VERSION 5.8 ;
BUSBITCHARS "[]" ;
DIVIDERCHAR "/" ;
UNITS
    DATABASE MICRONS 1000 ;
END UNITS

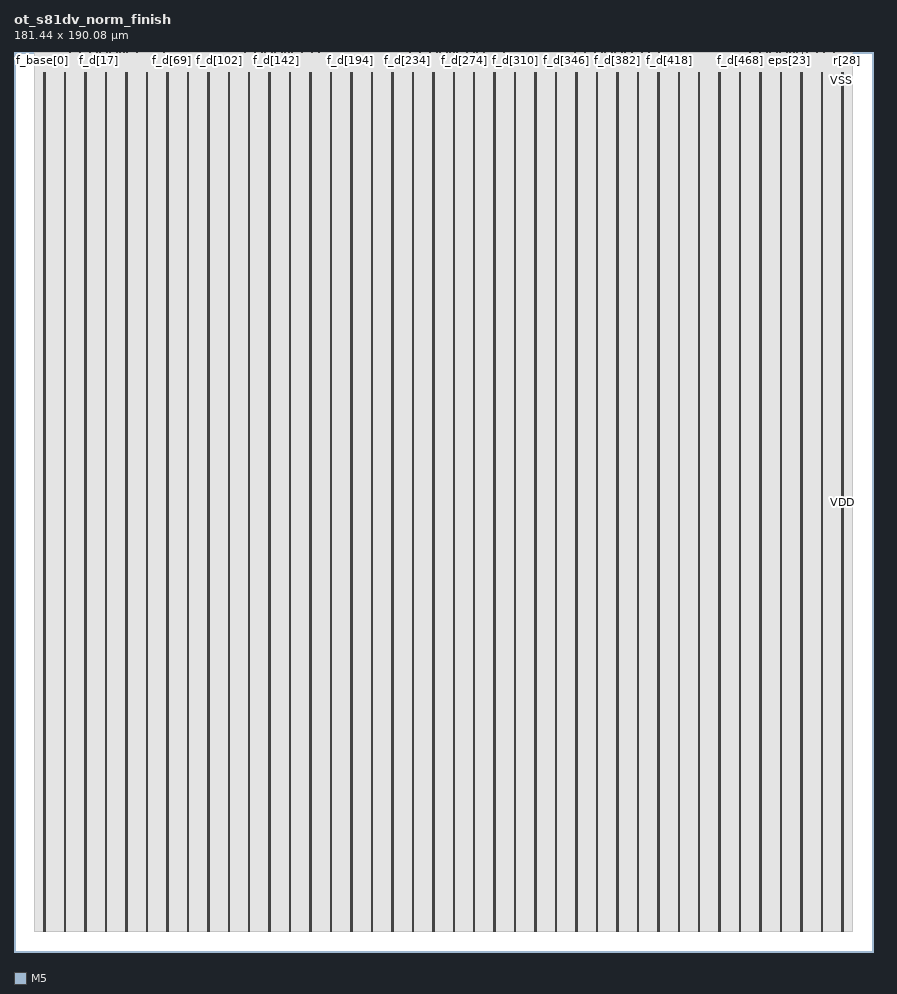
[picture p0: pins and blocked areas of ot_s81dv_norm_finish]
MACRO ot_s81dv_norm_finish
  FOREIGN ot_s81dv_norm_finish 0 0 ;
  CLASS BLOCK ;
  SIZE 181.44 BY 190.08 ;
  PIN clk
    DIRECTION INPUT ;
    USE SIGNAL ;
    PORT
      LAYER M5 ;
        RECT  166.548 189.6 166.596 190.08 ;
    END
  END clk
  PIN eps[0]
    DIRECTION INPUT ;
    USE SIGNAL ;
    PORT
      LAYER M5 ;
        RECT  156.96 189.996 156.984 190.08 ;
    END
  END eps[0]
  PIN eps[10]
    DIRECTION INPUT ;
    USE SIGNAL ;
    PORT
      LAYER M5 ;
        RECT  159.936 189.996 159.96 190.08 ;
    END
  END eps[10]
  PIN eps[11]
    DIRECTION INPUT ;
    USE SIGNAL ;
    PORT
      LAYER M5 ;
        RECT  160.224 189.996 160.248 190.08 ;
    END
  END eps[11]
  PIN eps[12]
    DIRECTION INPUT ;
    USE SIGNAL ;
    PORT
      LAYER M5 ;
        RECT  160.56 189.996 160.584 190.08 ;
    END
  END eps[12]
  PIN eps[13]
    DIRECTION INPUT ;
    USE SIGNAL ;
    PORT
      LAYER M5 ;
        RECT  160.848 189.996 160.872 190.08 ;
    END
  END eps[13]
  PIN eps[14]
    DIRECTION INPUT ;
    USE SIGNAL ;
    PORT
      LAYER M5 ;
        RECT  161.136 189.996 161.16 190.08 ;
    END
  END eps[14]
  PIN eps[15]
    DIRECTION INPUT ;
    USE SIGNAL ;
    PORT
      LAYER M5 ;
        RECT  161.472 189.996 161.496 190.08 ;
    END
  END eps[15]
  PIN eps[16]
    DIRECTION INPUT ;
    USE SIGNAL ;
    PORT
      LAYER M5 ;
        RECT  161.76 189.996 161.784 190.08 ;
    END
  END eps[16]
  PIN eps[17]
    DIRECTION INPUT ;
    USE SIGNAL ;
    PORT
      LAYER M5 ;
        RECT  162.048 189.996 162.072 190.08 ;
    END
  END eps[17]
  PIN eps[18]
    DIRECTION INPUT ;
    USE SIGNAL ;
    PORT
      LAYER M5 ;
        RECT  162.336 189.996 162.36 190.08 ;
    END
  END eps[18]
  PIN eps[19]
    DIRECTION INPUT ;
    USE SIGNAL ;
    PORT
      LAYER M5 ;
        RECT  162.672 189.996 162.696 190.08 ;
    END
  END eps[19]
  PIN eps[1]
    DIRECTION INPUT ;
    USE SIGNAL ;
    PORT
      LAYER M5 ;
        RECT  157.248 189.996 157.272 190.08 ;
    END
  END eps[1]
  PIN eps[20]
    DIRECTION INPUT ;
    USE SIGNAL ;
    PORT
      LAYER M5 ;
        RECT  162.96 189.996 162.984 190.08 ;
    END
  END eps[20]
  PIN eps[21]
    DIRECTION INPUT ;
    USE SIGNAL ;
    PORT
      LAYER M5 ;
        RECT  163.248 189.996 163.272 190.08 ;
    END
  END eps[21]
  PIN eps[22]
    DIRECTION INPUT ;
    USE SIGNAL ;
    PORT
      LAYER M5 ;
        RECT  163.536 189.996 163.56 190.08 ;
    END
  END eps[22]
  PIN eps[23]
    DIRECTION INPUT ;
    USE SIGNAL ;
    PORT
      LAYER M5 ;
        RECT  163.872 189.996 163.896 190.08 ;
    END
  END eps[23]
  PIN eps[24]
    DIRECTION INPUT ;
    USE SIGNAL ;
    PORT
      LAYER M5 ;
        RECT  164.16 189.996 164.184 190.08 ;
    END
  END eps[24]
  PIN eps[25]
    DIRECTION INPUT ;
    USE SIGNAL ;
    PORT
      LAYER M5 ;
        RECT  164.448 189.996 164.472 190.08 ;
    END
  END eps[25]
  PIN eps[26]
    DIRECTION INPUT ;
    USE SIGNAL ;
    PORT
      LAYER M5 ;
        RECT  164.736 189.996 164.76 190.08 ;
    END
  END eps[26]
  PIN eps[27]
    DIRECTION INPUT ;
    USE SIGNAL ;
    PORT
      LAYER M5 ;
        RECT  165.072 189.996 165.096 190.08 ;
    END
  END eps[27]
  PIN eps[28]
    DIRECTION INPUT ;
    USE SIGNAL ;
    PORT
      LAYER M5 ;
        RECT  165.36 189.996 165.384 190.08 ;
    END
  END eps[28]
  PIN eps[29]
    DIRECTION INPUT ;
    USE SIGNAL ;
    PORT
      LAYER M5 ;
        RECT  165.648 189.996 165.672 190.08 ;
    END
  END eps[29]
  PIN eps[2]
    DIRECTION INPUT ;
    USE SIGNAL ;
    PORT
      LAYER M5 ;
        RECT  157.536 189.996 157.56 190.08 ;
    END
  END eps[2]
  PIN eps[30]
    DIRECTION INPUT ;
    USE SIGNAL ;
    PORT
      LAYER M5 ;
        RECT  165.936 189.996 165.96 190.08 ;
    END
  END eps[30]
  PIN eps[31]
    DIRECTION INPUT ;
    USE SIGNAL ;
    PORT
      LAYER M5 ;
        RECT  166.272 189.996 166.296 190.08 ;
    END
  END eps[31]
  PIN eps[3]
    DIRECTION INPUT ;
    USE SIGNAL ;
    PORT
      LAYER M5 ;
        RECT  157.824 189.996 157.848 190.08 ;
    END
  END eps[3]
  PIN eps[4]
    DIRECTION INPUT ;
    USE SIGNAL ;
    PORT
      LAYER M5 ;
        RECT  158.16 189.996 158.184 190.08 ;
    END
  END eps[4]
  PIN eps[5]
    DIRECTION INPUT ;
    USE SIGNAL ;
    PORT
      LAYER M5 ;
        RECT  158.448 189.996 158.472 190.08 ;
    END
  END eps[5]
  PIN eps[6]
    DIRECTION INPUT ;
    USE SIGNAL ;
    PORT
      LAYER M5 ;
        RECT  158.736 189.996 158.76 190.08 ;
    END
  END eps[6]
  PIN eps[7]
    DIRECTION INPUT ;
    USE SIGNAL ;
    PORT
      LAYER M5 ;
        RECT  159.024 189.996 159.048 190.08 ;
    END
  END eps[7]
  PIN eps[8]
    DIRECTION INPUT ;
    USE SIGNAL ;
    PORT
      LAYER M5 ;
        RECT  159.36 189.996 159.384 190.08 ;
    END
  END eps[8]
  PIN eps[9]
    DIRECTION INPUT ;
    USE SIGNAL ;
    PORT
      LAYER M5 ;
        RECT  159.648 189.996 159.672 190.08 ;
    END
  END eps[9]
  PIN f_base[0]
    DIRECTION INPUT ;
    USE SIGNAL ;
    PORT
      LAYER M5 ;
        RECT  5.52 189.996 5.544 190.08 ;
    END
  END f_base[0]
  PIN f_base[10]
    DIRECTION INPUT ;
    USE SIGNAL ;
    PORT
      LAYER M5 ;
        RECT  8.544 189.996 8.568 190.08 ;
    END
  END f_base[10]
  PIN f_base[11]
    DIRECTION INPUT ;
    USE SIGNAL ;
    PORT
      LAYER M5 ;
        RECT  8.832 189.996 8.856 190.08 ;
    END
  END f_base[11]
  PIN f_base[12]
    DIRECTION INPUT ;
    USE SIGNAL ;
    PORT
      LAYER M5 ;
        RECT  9.12 189.996 9.144 190.08 ;
    END
  END f_base[12]
  PIN f_base[13]
    DIRECTION INPUT ;
    USE SIGNAL ;
    PORT
      LAYER M5 ;
        RECT  9.408 189.996 9.432 190.08 ;
    END
  END f_base[13]
  PIN f_base[14]
    DIRECTION INPUT ;
    USE SIGNAL ;
    PORT
      LAYER M5 ;
        RECT  9.744 189.996 9.768 190.08 ;
    END
  END f_base[14]
  PIN f_base[15]
    DIRECTION INPUT ;
    USE SIGNAL ;
    PORT
      LAYER M5 ;
        RECT  10.032 189.996 10.056 190.08 ;
    END
  END f_base[15]
  PIN f_base[16]
    DIRECTION INPUT ;
    USE SIGNAL ;
    PORT
      LAYER M5 ;
        RECT  10.32 189.996 10.344 190.08 ;
    END
  END f_base[16]
  PIN f_base[17]
    DIRECTION INPUT ;
    USE SIGNAL ;
    PORT
      LAYER M5 ;
        RECT  10.608 189.996 10.632 190.08 ;
    END
  END f_base[17]
  PIN f_base[18]
    DIRECTION INPUT ;
    USE SIGNAL ;
    PORT
      LAYER M5 ;
        RECT  10.944 189.996 10.968 190.08 ;
    END
  END f_base[18]
  PIN f_base[19]
    DIRECTION INPUT ;
    USE SIGNAL ;
    PORT
      LAYER M5 ;
        RECT  11.232 189.996 11.256 190.08 ;
    END
  END f_base[19]
  PIN f_base[1]
    DIRECTION INPUT ;
    USE SIGNAL ;
    PORT
      LAYER M5 ;
        RECT  5.808 189.996 5.832 190.08 ;
    END
  END f_base[1]
  PIN f_base[20]
    DIRECTION INPUT ;
    USE SIGNAL ;
    PORT
      LAYER M5 ;
        RECT  11.52 189.996 11.544 190.08 ;
    END
  END f_base[20]
  PIN f_base[21]
    DIRECTION INPUT ;
    USE SIGNAL ;
    PORT
      LAYER M5 ;
        RECT  11.808 189.996 11.832 190.08 ;
    END
  END f_base[21]
  PIN f_base[22]
    DIRECTION INPUT ;
    USE SIGNAL ;
    PORT
      LAYER M5 ;
        RECT  12.144 189.996 12.168 190.08 ;
    END
  END f_base[22]
  PIN f_base[23]
    DIRECTION INPUT ;
    USE SIGNAL ;
    PORT
      LAYER M5 ;
        RECT  12.432 189.996 12.456 190.08 ;
    END
  END f_base[23]
  PIN f_base[2]
    DIRECTION INPUT ;
    USE SIGNAL ;
    PORT
      LAYER M5 ;
        RECT  6.144 189.996 6.168 190.08 ;
    END
  END f_base[2]
  PIN f_base[3]
    DIRECTION INPUT ;
    USE SIGNAL ;
    PORT
      LAYER M5 ;
        RECT  6.432 189.996 6.456 190.08 ;
    END
  END f_base[3]
  PIN f_base[4]
    DIRECTION INPUT ;
    USE SIGNAL ;
    PORT
      LAYER M5 ;
        RECT  6.72 189.996 6.744 190.08 ;
    END
  END f_base[4]
  PIN f_base[5]
    DIRECTION INPUT ;
    USE SIGNAL ;
    PORT
      LAYER M5 ;
        RECT  7.008 189.996 7.032 190.08 ;
    END
  END f_base[5]
  PIN f_base[6]
    DIRECTION INPUT ;
    USE SIGNAL ;
    PORT
      LAYER M5 ;
        RECT  7.344 189.996 7.368 190.08 ;
    END
  END f_base[6]
  PIN f_base[7]
    DIRECTION INPUT ;
    USE SIGNAL ;
    PORT
      LAYER M5 ;
        RECT  7.632 189.996 7.656 190.08 ;
    END
  END f_base[7]
  PIN f_base[8]
    DIRECTION INPUT ;
    USE SIGNAL ;
    PORT
      LAYER M5 ;
        RECT  7.92 189.996 7.944 190.08 ;
    END
  END f_base[8]
  PIN f_base[9]
    DIRECTION INPUT ;
    USE SIGNAL ;
    PORT
      LAYER M5 ;
        RECT  8.208 189.996 8.232 190.08 ;
    END
  END f_base[9]
  PIN f_d[0]
    DIRECTION INPUT ;
    USE SIGNAL ;
    PORT
      LAYER M5 ;
        RECT  12.72 189.996 12.744 190.08 ;
    END
  END f_d[0]
  PIN f_d[100]
    DIRECTION INPUT ;
    USE SIGNAL ;
    PORT
      LAYER M5 ;
        RECT  42.768 189.996 42.792 190.08 ;
    END
  END f_d[100]
  PIN f_d[101]
    DIRECTION INPUT ;
    USE SIGNAL ;
    PORT
      LAYER M5 ;
        RECT  43.056 189.996 43.08 190.08 ;
    END
  END f_d[101]
  PIN f_d[102]
    DIRECTION INPUT ;
    USE SIGNAL ;
    PORT
      LAYER M5 ;
        RECT  43.392 189.996 43.416 190.08 ;
    END
  END f_d[102]
  PIN f_d[103]
    DIRECTION INPUT ;
    USE SIGNAL ;
    PORT
      LAYER M5 ;
        RECT  43.68 189.996 43.704 190.08 ;
    END
  END f_d[103]
  PIN f_d[104]
    DIRECTION INPUT ;
    USE SIGNAL ;
    PORT
      LAYER M5 ;
        RECT  43.968 189.996 43.992 190.08 ;
    END
  END f_d[104]
  PIN f_d[105]
    DIRECTION INPUT ;
    USE SIGNAL ;
    PORT
      LAYER M5 ;
        RECT  44.256 189.996 44.28 190.08 ;
    END
  END f_d[105]
  PIN f_d[106]
    DIRECTION INPUT ;
    USE SIGNAL ;
    PORT
      LAYER M5 ;
        RECT  44.592 189.996 44.616 190.08 ;
    END
  END f_d[106]
  PIN f_d[107]
    DIRECTION INPUT ;
    USE SIGNAL ;
    PORT
      LAYER M5 ;
        RECT  44.88 189.996 44.904 190.08 ;
    END
  END f_d[107]
  PIN f_d[108]
    DIRECTION INPUT ;
    USE SIGNAL ;
    PORT
      LAYER M5 ;
        RECT  45.168 189.996 45.192 190.08 ;
    END
  END f_d[108]
  PIN f_d[109]
    DIRECTION INPUT ;
    USE SIGNAL ;
    PORT
      LAYER M5 ;
        RECT  45.504 189.996 45.528 190.08 ;
    END
  END f_d[109]
  PIN f_d[10]
    DIRECTION INPUT ;
    USE SIGNAL ;
    PORT
      LAYER M5 ;
        RECT  15.744 189.996 15.768 190.08 ;
    END
  END f_d[10]
  PIN f_d[110]
    DIRECTION INPUT ;
    USE SIGNAL ;
    PORT
      LAYER M5 ;
        RECT  45.792 189.996 45.816 190.08 ;
    END
  END f_d[110]
  PIN f_d[111]
    DIRECTION INPUT ;
    USE SIGNAL ;
    PORT
      LAYER M5 ;
        RECT  46.08 189.996 46.104 190.08 ;
    END
  END f_d[111]
  PIN f_d[112]
    DIRECTION INPUT ;
    USE SIGNAL ;
    PORT
      LAYER M5 ;
        RECT  46.368 189.996 46.392 190.08 ;
    END
  END f_d[112]
  PIN f_d[113]
    DIRECTION INPUT ;
    USE SIGNAL ;
    PORT
      LAYER M5 ;
        RECT  46.704 189.996 46.728 190.08 ;
    END
  END f_d[113]
  PIN f_d[114]
    DIRECTION INPUT ;
    USE SIGNAL ;
    PORT
      LAYER M5 ;
        RECT  46.992 189.996 47.016 190.08 ;
    END
  END f_d[114]
  PIN f_d[115]
    DIRECTION INPUT ;
    USE SIGNAL ;
    PORT
      LAYER M5 ;
        RECT  47.28 189.996 47.304 190.08 ;
    END
  END f_d[115]
  PIN f_d[116]
    DIRECTION INPUT ;
    USE SIGNAL ;
    PORT
      LAYER M5 ;
        RECT  47.568 189.996 47.592 190.08 ;
    END
  END f_d[116]
  PIN f_d[117]
    DIRECTION INPUT ;
    USE SIGNAL ;
    PORT
      LAYER M5 ;
        RECT  47.904 189.996 47.928 190.08 ;
    END
  END f_d[117]
  PIN f_d[118]
    DIRECTION INPUT ;
    USE SIGNAL ;
    PORT
      LAYER M5 ;
        RECT  48.192 189.996 48.216 190.08 ;
    END
  END f_d[118]
  PIN f_d[119]
    DIRECTION INPUT ;
    USE SIGNAL ;
    PORT
      LAYER M5 ;
        RECT  48.48 189.996 48.504 190.08 ;
    END
  END f_d[119]
  PIN f_d[11]
    DIRECTION INPUT ;
    USE SIGNAL ;
    PORT
      LAYER M5 ;
        RECT  16.032 189.996 16.056 190.08 ;
    END
  END f_d[11]
  PIN f_d[120]
    DIRECTION INPUT ;
    USE SIGNAL ;
    PORT
      LAYER M5 ;
        RECT  48.768 189.996 48.792 190.08 ;
    END
  END f_d[120]
  PIN f_d[121]
    DIRECTION INPUT ;
    USE SIGNAL ;
    PORT
      LAYER M5 ;
        RECT  49.104 189.996 49.128 190.08 ;
    END
  END f_d[121]
  PIN f_d[122]
    DIRECTION INPUT ;
    USE SIGNAL ;
    PORT
      LAYER M5 ;
        RECT  49.392 189.996 49.416 190.08 ;
    END
  END f_d[122]
  PIN f_d[123]
    DIRECTION INPUT ;
    USE SIGNAL ;
    PORT
      LAYER M5 ;
        RECT  49.68 189.996 49.704 190.08 ;
    END
  END f_d[123]
  PIN f_d[124]
    DIRECTION INPUT ;
    USE SIGNAL ;
    PORT
      LAYER M5 ;
        RECT  49.968 189.996 49.992 190.08 ;
    END
  END f_d[124]
  PIN f_d[125]
    DIRECTION INPUT ;
    USE SIGNAL ;
    PORT
      LAYER M5 ;
        RECT  50.304 189.996 50.328 190.08 ;
    END
  END f_d[125]
  PIN f_d[126]
    DIRECTION INPUT ;
    USE SIGNAL ;
    PORT
      LAYER M5 ;
        RECT  50.592 189.996 50.616 190.08 ;
    END
  END f_d[126]
  PIN f_d[127]
    DIRECTION INPUT ;
    USE SIGNAL ;
    PORT
      LAYER M5 ;
        RECT  50.88 189.996 50.904 190.08 ;
    END
  END f_d[127]
  PIN f_d[128]
    DIRECTION INPUT ;
    USE SIGNAL ;
    PORT
      LAYER M5 ;
        RECT  51.168 189.996 51.192 190.08 ;
    END
  END f_d[128]
  PIN f_d[129]
    DIRECTION INPUT ;
    USE SIGNAL ;
    PORT
      LAYER M5 ;
        RECT  51.504 189.996 51.528 190.08 ;
    END
  END f_d[129]
  PIN f_d[12]
    DIRECTION INPUT ;
    USE SIGNAL ;
    PORT
      LAYER M5 ;
        RECT  16.32 189.996 16.344 190.08 ;
    END
  END f_d[12]
  PIN f_d[130]
    DIRECTION INPUT ;
    USE SIGNAL ;
    PORT
      LAYER M5 ;
        RECT  51.792 189.996 51.816 190.08 ;
    END
  END f_d[130]
  PIN f_d[131]
    DIRECTION INPUT ;
    USE SIGNAL ;
    PORT
      LAYER M5 ;
        RECT  52.08 189.996 52.104 190.08 ;
    END
  END f_d[131]
  PIN f_d[132]
    DIRECTION INPUT ;
    USE SIGNAL ;
    PORT
      LAYER M5 ;
        RECT  52.368 189.996 52.392 190.08 ;
    END
  END f_d[132]
  PIN f_d[133]
    DIRECTION INPUT ;
    USE SIGNAL ;
    PORT
      LAYER M5 ;
        RECT  52.704 189.996 52.728 190.08 ;
    END
  END f_d[133]
  PIN f_d[134]
    DIRECTION INPUT ;
    USE SIGNAL ;
    PORT
      LAYER M5 ;
        RECT  52.992 189.996 53.016 190.08 ;
    END
  END f_d[134]
  PIN f_d[135]
    DIRECTION INPUT ;
    USE SIGNAL ;
    PORT
      LAYER M5 ;
        RECT  53.28 189.996 53.304 190.08 ;
    END
  END f_d[135]
  PIN f_d[136]
    DIRECTION INPUT ;
    USE SIGNAL ;
    PORT
      LAYER M5 ;
        RECT  53.568 189.996 53.592 190.08 ;
    END
  END f_d[136]
  PIN f_d[137]
    DIRECTION INPUT ;
    USE SIGNAL ;
    PORT
      LAYER M5 ;
        RECT  53.904 189.996 53.928 190.08 ;
    END
  END f_d[137]
  PIN f_d[138]
    DIRECTION INPUT ;
    USE SIGNAL ;
    PORT
      LAYER M5 ;
        RECT  54.192 189.996 54.216 190.08 ;
    END
  END f_d[138]
  PIN f_d[139]
    DIRECTION INPUT ;
    USE SIGNAL ;
    PORT
      LAYER M5 ;
        RECT  54.48 189.996 54.504 190.08 ;
    END
  END f_d[139]
  PIN f_d[13]
    DIRECTION INPUT ;
    USE SIGNAL ;
    PORT
      LAYER M5 ;
        RECT  16.656 189.996 16.68 190.08 ;
    END
  END f_d[13]
  PIN f_d[140]
    DIRECTION INPUT ;
    USE SIGNAL ;
    PORT
      LAYER M5 ;
        RECT  54.816 189.996 54.84 190.08 ;
    END
  END f_d[140]
  PIN f_d[141]
    DIRECTION INPUT ;
    USE SIGNAL ;
    PORT
      LAYER M5 ;
        RECT  55.104 189.996 55.128 190.08 ;
    END
  END f_d[141]
  PIN f_d[142]
    DIRECTION INPUT ;
    USE SIGNAL ;
    PORT
      LAYER M5 ;
        RECT  55.392 189.996 55.416 190.08 ;
    END
  END f_d[142]
  PIN f_d[143]
    DIRECTION INPUT ;
    USE SIGNAL ;
    PORT
      LAYER M5 ;
        RECT  55.68 189.996 55.704 190.08 ;
    END
  END f_d[143]
  PIN f_d[144]
    DIRECTION INPUT ;
    USE SIGNAL ;
    PORT
      LAYER M5 ;
        RECT  56.016 189.996 56.04 190.08 ;
    END
  END f_d[144]
  PIN f_d[145]
    DIRECTION INPUT ;
    USE SIGNAL ;
    PORT
      LAYER M5 ;
        RECT  56.304 189.996 56.328 190.08 ;
    END
  END f_d[145]
  PIN f_d[146]
    DIRECTION INPUT ;
    USE SIGNAL ;
    PORT
      LAYER M5 ;
        RECT  56.592 189.996 56.616 190.08 ;
    END
  END f_d[146]
  PIN f_d[147]
    DIRECTION INPUT ;
    USE SIGNAL ;
    PORT
      LAYER M5 ;
        RECT  56.88 189.996 56.904 190.08 ;
    END
  END f_d[147]
  PIN f_d[148]
    DIRECTION INPUT ;
    USE SIGNAL ;
    PORT
      LAYER M5 ;
        RECT  57.216 189.996 57.24 190.08 ;
    END
  END f_d[148]
  PIN f_d[149]
    DIRECTION INPUT ;
    USE SIGNAL ;
    PORT
      LAYER M5 ;
        RECT  57.504 189.996 57.528 190.08 ;
    END
  END f_d[149]
  PIN f_d[14]
    DIRECTION INPUT ;
    USE SIGNAL ;
    PORT
      LAYER M5 ;
        RECT  16.944 189.996 16.968 190.08 ;
    END
  END f_d[14]
  PIN f_d[150]
    DIRECTION INPUT ;
    USE SIGNAL ;
    PORT
      LAYER M5 ;
        RECT  57.792 189.996 57.816 190.08 ;
    END
  END f_d[150]
  PIN f_d[151]
    DIRECTION INPUT ;
    USE SIGNAL ;
    PORT
      LAYER M5 ;
        RECT  58.08 189.996 58.104 190.08 ;
    END
  END f_d[151]
  PIN f_d[152]
    DIRECTION INPUT ;
    USE SIGNAL ;
    PORT
      LAYER M5 ;
        RECT  58.416 189.996 58.44 190.08 ;
    END
  END f_d[152]
  PIN f_d[153]
    DIRECTION INPUT ;
    USE SIGNAL ;
    PORT
      LAYER M5 ;
        RECT  58.704 189.996 58.728 190.08 ;
    END
  END f_d[153]
  PIN f_d[154]
    DIRECTION INPUT ;
    USE SIGNAL ;
    PORT
      LAYER M5 ;
        RECT  58.992 189.996 59.016 190.08 ;
    END
  END f_d[154]
  PIN f_d[155]
    DIRECTION INPUT ;
    USE SIGNAL ;
    PORT
      LAYER M5 ;
        RECT  59.28 189.996 59.304 190.08 ;
    END
  END f_d[155]
  PIN f_d[156]
    DIRECTION INPUT ;
    USE SIGNAL ;
    PORT
      LAYER M5 ;
        RECT  59.616 189.996 59.64 190.08 ;
    END
  END f_d[156]
  PIN f_d[157]
    DIRECTION INPUT ;
    USE SIGNAL ;
    PORT
      LAYER M5 ;
        RECT  59.904 189.996 59.928 190.08 ;
    END
  END f_d[157]
  PIN f_d[158]
    DIRECTION INPUT ;
    USE SIGNAL ;
    PORT
      LAYER M5 ;
        RECT  60.192 189.996 60.216 190.08 ;
    END
  END f_d[158]
  PIN f_d[159]
    DIRECTION INPUT ;
    USE SIGNAL ;
    PORT
      LAYER M5 ;
        RECT  60.48 189.996 60.504 190.08 ;
    END
  END f_d[159]
  PIN f_d[15]
    DIRECTION INPUT ;
    USE SIGNAL ;
    PORT
      LAYER M5 ;
        RECT  17.232 189.996 17.256 190.08 ;
    END
  END f_d[15]
  PIN f_d[160]
    DIRECTION INPUT ;
    USE SIGNAL ;
    PORT
      LAYER M5 ;
        RECT  60.816 189.996 60.84 190.08 ;
    END
  END f_d[160]
  PIN f_d[161]
    DIRECTION INPUT ;
    USE SIGNAL ;
    PORT
      LAYER M5 ;
        RECT  61.104 189.996 61.128 190.08 ;
    END
  END f_d[161]
  PIN f_d[162]
    DIRECTION INPUT ;
    USE SIGNAL ;
    PORT
      LAYER M5 ;
        RECT  61.392 189.996 61.416 190.08 ;
    END
  END f_d[162]
  PIN f_d[163]
    DIRECTION INPUT ;
    USE SIGNAL ;
    PORT
      LAYER M5 ;
        RECT  61.68 189.996 61.704 190.08 ;
    END
  END f_d[163]
  PIN f_d[164]
    DIRECTION INPUT ;
    USE SIGNAL ;
    PORT
      LAYER M5 ;
        RECT  62.016 189.996 62.04 190.08 ;
    END
  END f_d[164]
  PIN f_d[165]
    DIRECTION INPUT ;
    USE SIGNAL ;
    PORT
      LAYER M5 ;
        RECT  62.304 189.996 62.328 190.08 ;
    END
  END f_d[165]
  PIN f_d[166]
    DIRECTION INPUT ;
    USE SIGNAL ;
    PORT
      LAYER M5 ;
        RECT  62.592 189.996 62.616 190.08 ;
    END
  END f_d[166]
  PIN f_d[167]
    DIRECTION INPUT ;
    USE SIGNAL ;
    PORT
      LAYER M5 ;
        RECT  62.928 189.996 62.952 190.08 ;
    END
  END f_d[167]
  PIN f_d[168]
    DIRECTION INPUT ;
    USE SIGNAL ;
    PORT
      LAYER M5 ;
        RECT  63.216 189.996 63.24 190.08 ;
    END
  END f_d[168]
  PIN f_d[169]
    DIRECTION INPUT ;
    USE SIGNAL ;
    PORT
      LAYER M5 ;
        RECT  63.504 189.996 63.528 190.08 ;
    END
  END f_d[169]
  PIN f_d[16]
    DIRECTION INPUT ;
    USE SIGNAL ;
    PORT
      LAYER M5 ;
        RECT  17.52 189.996 17.544 190.08 ;
    END
  END f_d[16]
  PIN f_d[170]
    DIRECTION INPUT ;
    USE SIGNAL ;
    PORT
      LAYER M5 ;
        RECT  63.792 189.996 63.816 190.08 ;
    END
  END f_d[170]
  PIN f_d[171]
    DIRECTION INPUT ;
    USE SIGNAL ;
    PORT
      LAYER M5 ;
        RECT  64.128 189.996 64.152 190.08 ;
    END
  END f_d[171]
  PIN f_d[172]
    DIRECTION INPUT ;
    USE SIGNAL ;
    PORT
      LAYER M5 ;
        RECT  64.416 189.996 64.44 190.08 ;
    END
  END f_d[172]
  PIN f_d[173]
    DIRECTION INPUT ;
    USE SIGNAL ;
    PORT
      LAYER M5 ;
        RECT  64.704 189.996 64.728 190.08 ;
    END
  END f_d[173]
  PIN f_d[174]
    DIRECTION INPUT ;
    USE SIGNAL ;
    PORT
      LAYER M5 ;
        RECT  64.992 189.996 65.016 190.08 ;
    END
  END f_d[174]
  PIN f_d[175]
    DIRECTION INPUT ;
    USE SIGNAL ;
    PORT
      LAYER M5 ;
        RECT  65.328 189.996 65.352 190.08 ;
    END
  END f_d[175]
  PIN f_d[176]
    DIRECTION INPUT ;
    USE SIGNAL ;
    PORT
      LAYER M5 ;
        RECT  65.616 189.996 65.64 190.08 ;
    END
  END f_d[176]
  PIN f_d[177]
    DIRECTION INPUT ;
    USE SIGNAL ;
    PORT
      LAYER M5 ;
        RECT  65.904 189.996 65.928 190.08 ;
    END
  END f_d[177]
  PIN f_d[178]
    DIRECTION INPUT ;
    USE SIGNAL ;
    PORT
      LAYER M5 ;
        RECT  66.192 189.996 66.216 190.08 ;
    END
  END f_d[178]
  PIN f_d[179]
    DIRECTION INPUT ;
    USE SIGNAL ;
    PORT
      LAYER M5 ;
        RECT  66.528 189.996 66.552 190.08 ;
    END
  END f_d[179]
  PIN f_d[17]
    DIRECTION INPUT ;
    USE SIGNAL ;
    PORT
      LAYER M5 ;
        RECT  17.856 189.996 17.88 190.08 ;
    END
  END f_d[17]
  PIN f_d[180]
    DIRECTION INPUT ;
    USE SIGNAL ;
    PORT
      LAYER M5 ;
        RECT  66.816 189.996 66.84 190.08 ;
    END
  END f_d[180]
  PIN f_d[181]
    DIRECTION INPUT ;
    USE SIGNAL ;
    PORT
      LAYER M5 ;
        RECT  67.104 189.996 67.128 190.08 ;
    END
  END f_d[181]
  PIN f_d[182]
    DIRECTION INPUT ;
    USE SIGNAL ;
    PORT
      LAYER M5 ;
        RECT  67.392 189.996 67.416 190.08 ;
    END
  END f_d[182]
  PIN f_d[183]
    DIRECTION INPUT ;
    USE SIGNAL ;
    PORT
      LAYER M5 ;
        RECT  67.728 189.996 67.752 190.08 ;
    END
  END f_d[183]
  PIN f_d[184]
    DIRECTION INPUT ;
    USE SIGNAL ;
    PORT
      LAYER M5 ;
        RECT  68.016 189.996 68.04 190.08 ;
    END
  END f_d[184]
  PIN f_d[185]
    DIRECTION INPUT ;
    USE SIGNAL ;
    PORT
      LAYER M5 ;
        RECT  68.304 189.996 68.328 190.08 ;
    END
  END f_d[185]
  PIN f_d[186]
    DIRECTION INPUT ;
    USE SIGNAL ;
    PORT
      LAYER M5 ;
        RECT  68.592 189.996 68.616 190.08 ;
    END
  END f_d[186]
  PIN f_d[187]
    DIRECTION INPUT ;
    USE SIGNAL ;
    PORT
      LAYER M5 ;
        RECT  68.928 189.996 68.952 190.08 ;
    END
  END f_d[187]
  PIN f_d[188]
    DIRECTION INPUT ;
    USE SIGNAL ;
    PORT
      LAYER M5 ;
        RECT  69.216 189.996 69.24 190.08 ;
    END
  END f_d[188]
  PIN f_d[189]
    DIRECTION INPUT ;
    USE SIGNAL ;
    PORT
      LAYER M5 ;
        RECT  69.504 189.996 69.528 190.08 ;
    END
  END f_d[189]
  PIN f_d[18]
    DIRECTION INPUT ;
    USE SIGNAL ;
    PORT
      LAYER M5 ;
        RECT  18.144 189.996 18.168 190.08 ;
    END
  END f_d[18]
  PIN f_d[190]
    DIRECTION INPUT ;
    USE SIGNAL ;
    PORT
      LAYER M5 ;
        RECT  69.792 189.996 69.816 190.08 ;
    END
  END f_d[190]
  PIN f_d[191]
    DIRECTION INPUT ;
    USE SIGNAL ;
    PORT
      LAYER M5 ;
        RECT  70.128 189.996 70.152 190.08 ;
    END
  END f_d[191]
  PIN f_d[192]
    DIRECTION INPUT ;
    USE SIGNAL ;
    PORT
      LAYER M5 ;
        RECT  70.416 189.996 70.44 190.08 ;
    END
  END f_d[192]
  PIN f_d[193]
    DIRECTION INPUT ;
    USE SIGNAL ;
    PORT
      LAYER M5 ;
        RECT  70.704 189.996 70.728 190.08 ;
    END
  END f_d[193]
  PIN f_d[194]
    DIRECTION INPUT ;
    USE SIGNAL ;
    PORT
      LAYER M5 ;
        RECT  71.04 189.996 71.064 190.08 ;
    END
  END f_d[194]
  PIN f_d[195]
    DIRECTION INPUT ;
    USE SIGNAL ;
    PORT
      LAYER M5 ;
        RECT  71.328 189.996 71.352 190.08 ;
    END
  END f_d[195]
  PIN f_d[196]
    DIRECTION INPUT ;
    USE SIGNAL ;
    PORT
      LAYER M5 ;
        RECT  71.616 189.996 71.64 190.08 ;
    END
  END f_d[196]
  PIN f_d[197]
    DIRECTION INPUT ;
    USE SIGNAL ;
    PORT
      LAYER M5 ;
        RECT  71.904 189.996 71.928 190.08 ;
    END
  END f_d[197]
  PIN f_d[198]
    DIRECTION INPUT ;
    USE SIGNAL ;
    PORT
      LAYER M5 ;
        RECT  72.24 189.996 72.264 190.08 ;
    END
  END f_d[198]
  PIN f_d[199]
    DIRECTION INPUT ;
    USE SIGNAL ;
    PORT
      LAYER M5 ;
        RECT  72.528 189.996 72.552 190.08 ;
    END
  END f_d[199]
  PIN f_d[19]
    DIRECTION INPUT ;
    USE SIGNAL ;
    PORT
      LAYER M5 ;
        RECT  18.432 189.996 18.456 190.08 ;
    END
  END f_d[19]
  PIN f_d[1]
    DIRECTION INPUT ;
    USE SIGNAL ;
    PORT
      LAYER M5 ;
        RECT  13.056 189.996 13.08 190.08 ;
    END
  END f_d[1]
  PIN f_d[200]
    DIRECTION INPUT ;
    USE SIGNAL ;
    PORT
      LAYER M5 ;
        RECT  72.816 189.996 72.84 190.08 ;
    END
  END f_d[200]
  PIN f_d[201]
    DIRECTION INPUT ;
    USE SIGNAL ;
    PORT
      LAYER M5 ;
        RECT  73.104 189.996 73.128 190.08 ;
    END
  END f_d[201]
  PIN f_d[202]
    DIRECTION INPUT ;
    USE SIGNAL ;
    PORT
      LAYER M5 ;
        RECT  73.44 189.996 73.464 190.08 ;
    END
  END f_d[202]
  PIN f_d[203]
    DIRECTION INPUT ;
    USE SIGNAL ;
    PORT
      LAYER M5 ;
        RECT  73.728 189.996 73.752 190.08 ;
    END
  END f_d[203]
  PIN f_d[204]
    DIRECTION INPUT ;
    USE SIGNAL ;
    PORT
      LAYER M5 ;
        RECT  74.016 189.996 74.04 190.08 ;
    END
  END f_d[204]
  PIN f_d[205]
    DIRECTION INPUT ;
    USE SIGNAL ;
    PORT
      LAYER M5 ;
        RECT  74.304 189.996 74.328 190.08 ;
    END
  END f_d[205]
  PIN f_d[206]
    DIRECTION INPUT ;
    USE SIGNAL ;
    PORT
      LAYER M5 ;
        RECT  74.64 189.996 74.664 190.08 ;
    END
  END f_d[206]
  PIN f_d[207]
    DIRECTION INPUT ;
    USE SIGNAL ;
    PORT
      LAYER M5 ;
        RECT  74.928 189.996 74.952 190.08 ;
    END
  END f_d[207]
  PIN f_d[208]
    DIRECTION INPUT ;
    USE SIGNAL ;
    PORT
      LAYER M5 ;
        RECT  75.216 189.996 75.24 190.08 ;
    END
  END f_d[208]
  PIN f_d[209]
    DIRECTION INPUT ;
    USE SIGNAL ;
    PORT
      LAYER M5 ;
        RECT  75.504 189.996 75.528 190.08 ;
    END
  END f_d[209]
  PIN f_d[20]
    DIRECTION INPUT ;
    USE SIGNAL ;
    PORT
      LAYER M5 ;
        RECT  18.72 189.996 18.744 190.08 ;
    END
  END f_d[20]
  PIN f_d[210]
    DIRECTION INPUT ;
    USE SIGNAL ;
    PORT
      LAYER M5 ;
        RECT  75.84 189.996 75.864 190.08 ;
    END
  END f_d[210]
  PIN f_d[211]
    DIRECTION INPUT ;
    USE SIGNAL ;
    PORT
      LAYER M5 ;
        RECT  76.128 189.996 76.152 190.08 ;
    END
  END f_d[211]
  PIN f_d[212]
    DIRECTION INPUT ;
    USE SIGNAL ;
    PORT
      LAYER M5 ;
        RECT  76.416 189.996 76.44 190.08 ;
    END
  END f_d[212]
  PIN f_d[213]
    DIRECTION INPUT ;
    USE SIGNAL ;
    PORT
      LAYER M5 ;
        RECT  76.704 189.996 76.728 190.08 ;
    END
  END f_d[213]
  PIN f_d[214]
    DIRECTION INPUT ;
    USE SIGNAL ;
    PORT
      LAYER M5 ;
        RECT  77.04 189.996 77.064 190.08 ;
    END
  END f_d[214]
  PIN f_d[215]
    DIRECTION INPUT ;
    USE SIGNAL ;
    PORT
      LAYER M5 ;
        RECT  77.328 189.996 77.352 190.08 ;
    END
  END f_d[215]
  PIN f_d[216]
    DIRECTION INPUT ;
    USE SIGNAL ;
    PORT
      LAYER M5 ;
        RECT  77.616 189.996 77.64 190.08 ;
    END
  END f_d[216]
  PIN f_d[217]
    DIRECTION INPUT ;
    USE SIGNAL ;
    PORT
      LAYER M5 ;
        RECT  77.904 189.996 77.928 190.08 ;
    END
  END f_d[217]
  PIN f_d[218]
    DIRECTION INPUT ;
    USE SIGNAL ;
    PORT
      LAYER M5 ;
        RECT  78.24 189.996 78.264 190.08 ;
    END
  END f_d[218]
  PIN f_d[219]
    DIRECTION INPUT ;
    USE SIGNAL ;
    PORT
      LAYER M5 ;
        RECT  78.528 189.996 78.552 190.08 ;
    END
  END f_d[219]
  PIN f_d[21]
    DIRECTION INPUT ;
    USE SIGNAL ;
    PORT
      LAYER M5 ;
        RECT  19.056 189.996 19.08 190.08 ;
    END
  END f_d[21]
  PIN f_d[220]
    DIRECTION INPUT ;
    USE SIGNAL ;
    PORT
      LAYER M5 ;
        RECT  78.816 189.996 78.84 190.08 ;
    END
  END f_d[220]
  PIN f_d[221]
    DIRECTION INPUT ;
    USE SIGNAL ;
    PORT
      LAYER M5 ;
        RECT  79.152 189.996 79.176 190.08 ;
    END
  END f_d[221]
  PIN f_d[222]
    DIRECTION INPUT ;
    USE SIGNAL ;
    PORT
      LAYER M5 ;
        RECT  79.44 189.996 79.464 190.08 ;
    END
  END f_d[222]
  PIN f_d[223]
    DIRECTION INPUT ;
    USE SIGNAL ;
    PORT
      LAYER M5 ;
        RECT  79.728 189.996 79.752 190.08 ;
    END
  END f_d[223]
  PIN f_d[224]
    DIRECTION INPUT ;
    USE SIGNAL ;
    PORT
      LAYER M5 ;
        RECT  80.016 189.996 80.04 190.08 ;
    END
  END f_d[224]
  PIN f_d[225]
    DIRECTION INPUT ;
    USE SIGNAL ;
    PORT
      LAYER M5 ;
        RECT  80.352 189.996 80.376 190.08 ;
    END
  END f_d[225]
  PIN f_d[226]
    DIRECTION INPUT ;
    USE SIGNAL ;
    PORT
      LAYER M5 ;
        RECT  80.64 189.996 80.664 190.08 ;
    END
  END f_d[226]
  PIN f_d[227]
    DIRECTION INPUT ;
    USE SIGNAL ;
    PORT
      LAYER M5 ;
        RECT  80.928 189.996 80.952 190.08 ;
    END
  END f_d[227]
  PIN f_d[228]
    DIRECTION INPUT ;
    USE SIGNAL ;
    PORT
      LAYER M5 ;
        RECT  81.216 189.996 81.24 190.08 ;
    END
  END f_d[228]
  PIN f_d[229]
    DIRECTION INPUT ;
    USE SIGNAL ;
    PORT
      LAYER M5 ;
        RECT  81.552 189.996 81.576 190.08 ;
    END
  END f_d[229]
  PIN f_d[22]
    DIRECTION INPUT ;
    USE SIGNAL ;
    PORT
      LAYER M5 ;
        RECT  19.344 189.996 19.368 190.08 ;
    END
  END f_d[22]
  PIN f_d[230]
    DIRECTION INPUT ;
    USE SIGNAL ;
    PORT
      LAYER M5 ;
        RECT  81.84 189.996 81.864 190.08 ;
    END
  END f_d[230]
  PIN f_d[231]
    DIRECTION INPUT ;
    USE SIGNAL ;
    PORT
      LAYER M5 ;
        RECT  82.128 189.996 82.152 190.08 ;
    END
  END f_d[231]
  PIN f_d[232]
    DIRECTION INPUT ;
    USE SIGNAL ;
    PORT
      LAYER M5 ;
        RECT  82.416 189.996 82.44 190.08 ;
    END
  END f_d[232]
  PIN f_d[233]
    DIRECTION INPUT ;
    USE SIGNAL ;
    PORT
      LAYER M5 ;
        RECT  82.752 189.996 82.776 190.08 ;
    END
  END f_d[233]
  PIN f_d[234]
    DIRECTION INPUT ;
    USE SIGNAL ;
    PORT
      LAYER M5 ;
        RECT  83.04 189.996 83.064 190.08 ;
    END
  END f_d[234]
  PIN f_d[235]
    DIRECTION INPUT ;
    USE SIGNAL ;
    PORT
      LAYER M5 ;
        RECT  83.328 189.996 83.352 190.08 ;
    END
  END f_d[235]
  PIN f_d[236]
    DIRECTION INPUT ;
    USE SIGNAL ;
    PORT
      LAYER M5 ;
        RECT  83.616 189.996 83.64 190.08 ;
    END
  END f_d[236]
  PIN f_d[237]
    DIRECTION INPUT ;
    USE SIGNAL ;
    PORT
      LAYER M5 ;
        RECT  83.952 189.996 83.976 190.08 ;
    END
  END f_d[237]
  PIN f_d[238]
    DIRECTION INPUT ;
    USE SIGNAL ;
    PORT
      LAYER M5 ;
        RECT  84.24 189.996 84.264 190.08 ;
    END
  END f_d[238]
  PIN f_d[239]
    DIRECTION INPUT ;
    USE SIGNAL ;
    PORT
      LAYER M5 ;
        RECT  84.528 189.996 84.552 190.08 ;
    END
  END f_d[239]
  PIN f_d[23]
    DIRECTION INPUT ;
    USE SIGNAL ;
    PORT
      LAYER M5 ;
        RECT  19.632 189.996 19.656 190.08 ;
    END
  END f_d[23]
  PIN f_d[240]
    DIRECTION INPUT ;
    USE SIGNAL ;
    PORT
      LAYER M5 ;
        RECT  84.816 189.996 84.84 190.08 ;
    END
  END f_d[240]
  PIN f_d[241]
    DIRECTION INPUT ;
    USE SIGNAL ;
    PORT
      LAYER M5 ;
        RECT  85.152 189.996 85.176 190.08 ;
    END
  END f_d[241]
  PIN f_d[242]
    DIRECTION INPUT ;
    USE SIGNAL ;
    PORT
      LAYER M5 ;
        RECT  85.44 189.996 85.464 190.08 ;
    END
  END f_d[242]
  PIN f_d[243]
    DIRECTION INPUT ;
    USE SIGNAL ;
    PORT
      LAYER M5 ;
        RECT  85.728 189.996 85.752 190.08 ;
    END
  END f_d[243]
  PIN f_d[244]
    DIRECTION INPUT ;
    USE SIGNAL ;
    PORT
      LAYER M5 ;
        RECT  86.016 189.996 86.04 190.08 ;
    END
  END f_d[244]
  PIN f_d[245]
    DIRECTION INPUT ;
    USE SIGNAL ;
    PORT
      LAYER M5 ;
        RECT  86.352 189.996 86.376 190.08 ;
    END
  END f_d[245]
  PIN f_d[246]
    DIRECTION INPUT ;
    USE SIGNAL ;
    PORT
      LAYER M5 ;
        RECT  86.64 189.996 86.664 190.08 ;
    END
  END f_d[246]
  PIN f_d[247]
    DIRECTION INPUT ;
    USE SIGNAL ;
    PORT
      LAYER M5 ;
        RECT  86.928 189.996 86.952 190.08 ;
    END
  END f_d[247]
  PIN f_d[248]
    DIRECTION INPUT ;
    USE SIGNAL ;
    PORT
      LAYER M5 ;
        RECT  87.264 189.996 87.288 190.08 ;
    END
  END f_d[248]
  PIN f_d[249]
    DIRECTION INPUT ;
    USE SIGNAL ;
    PORT
      LAYER M5 ;
        RECT  87.552 189.996 87.576 190.08 ;
    END
  END f_d[249]
  PIN f_d[24]
    DIRECTION INPUT ;
    USE SIGNAL ;
    PORT
      LAYER M5 ;
        RECT  19.92 189.996 19.944 190.08 ;
    END
  END f_d[24]
  PIN f_d[250]
    DIRECTION INPUT ;
    USE SIGNAL ;
    PORT
      LAYER M5 ;
        RECT  87.84 189.996 87.864 190.08 ;
    END
  END f_d[250]
  PIN f_d[251]
    DIRECTION INPUT ;
    USE SIGNAL ;
    PORT
      LAYER M5 ;
        RECT  88.128 189.996 88.152 190.08 ;
    END
  END f_d[251]
  PIN f_d[252]
    DIRECTION INPUT ;
    USE SIGNAL ;
    PORT
      LAYER M5 ;
        RECT  88.464 189.996 88.488 190.08 ;
    END
  END f_d[252]
  PIN f_d[253]
    DIRECTION INPUT ;
    USE SIGNAL ;
    PORT
      LAYER M5 ;
        RECT  88.752 189.996 88.776 190.08 ;
    END
  END f_d[253]
  PIN f_d[254]
    DIRECTION INPUT ;
    USE SIGNAL ;
    PORT
      LAYER M5 ;
        RECT  89.04 189.996 89.064 190.08 ;
    END
  END f_d[254]
  PIN f_d[255]
    DIRECTION INPUT ;
    USE SIGNAL ;
    PORT
      LAYER M5 ;
        RECT  89.328 189.996 89.352 190.08 ;
    END
  END f_d[255]
  PIN f_d[256]
    DIRECTION INPUT ;
    USE SIGNAL ;
    PORT
      LAYER M5 ;
        RECT  89.664 189.996 89.688 190.08 ;
    END
  END f_d[256]
  PIN f_d[257]
    DIRECTION INPUT ;
    USE SIGNAL ;
    PORT
      LAYER M5 ;
        RECT  89.952 189.996 89.976 190.08 ;
    END
  END f_d[257]
  PIN f_d[258]
    DIRECTION INPUT ;
    USE SIGNAL ;
    PORT
      LAYER M5 ;
        RECT  90.24 189.996 90.264 190.08 ;
    END
  END f_d[258]
  PIN f_d[259]
    DIRECTION INPUT ;
    USE SIGNAL ;
    PORT
      LAYER M5 ;
        RECT  90.528 189.996 90.552 190.08 ;
    END
  END f_d[259]
  PIN f_d[25]
    DIRECTION INPUT ;
    USE SIGNAL ;
    PORT
      LAYER M5 ;
        RECT  20.256 189.996 20.28 190.08 ;
    END
  END f_d[25]
  PIN f_d[260]
    DIRECTION INPUT ;
    USE SIGNAL ;
    PORT
      LAYER M5 ;
        RECT  90.864 189.996 90.888 190.08 ;
    END
  END f_d[260]
  PIN f_d[261]
    DIRECTION INPUT ;
    USE SIGNAL ;
    PORT
      LAYER M5 ;
        RECT  91.152 189.996 91.176 190.08 ;
    END
  END f_d[261]
  PIN f_d[262]
    DIRECTION INPUT ;
    USE SIGNAL ;
    PORT
      LAYER M5 ;
        RECT  91.44 189.996 91.464 190.08 ;
    END
  END f_d[262]
  PIN f_d[263]
    DIRECTION INPUT ;
    USE SIGNAL ;
    PORT
      LAYER M5 ;
        RECT  91.728 189.996 91.752 190.08 ;
    END
  END f_d[263]
  PIN f_d[264]
    DIRECTION INPUT ;
    USE SIGNAL ;
    PORT
      LAYER M5 ;
        RECT  92.064 189.996 92.088 190.08 ;
    END
  END f_d[264]
  PIN f_d[265]
    DIRECTION INPUT ;
    USE SIGNAL ;
    PORT
      LAYER M5 ;
        RECT  92.352 189.996 92.376 190.08 ;
    END
  END f_d[265]
  PIN f_d[266]
    DIRECTION INPUT ;
    USE SIGNAL ;
    PORT
      LAYER M5 ;
        RECT  92.64 189.996 92.664 190.08 ;
    END
  END f_d[266]
  PIN f_d[267]
    DIRECTION INPUT ;
    USE SIGNAL ;
    PORT
      LAYER M5 ;
        RECT  92.928 189.996 92.952 190.08 ;
    END
  END f_d[267]
  PIN f_d[268]
    DIRECTION INPUT ;
    USE SIGNAL ;
    PORT
      LAYER M5 ;
        RECT  93.264 189.996 93.288 190.08 ;
    END
  END f_d[268]
  PIN f_d[269]
    DIRECTION INPUT ;
    USE SIGNAL ;
    PORT
      LAYER M5 ;
        RECT  93.552 189.996 93.576 190.08 ;
    END
  END f_d[269]
  PIN f_d[26]
    DIRECTION INPUT ;
    USE SIGNAL ;
    PORT
      LAYER M5 ;
        RECT  20.544 189.996 20.568 190.08 ;
    END
  END f_d[26]
  PIN f_d[270]
    DIRECTION INPUT ;
    USE SIGNAL ;
    PORT
      LAYER M5 ;
        RECT  93.84 189.996 93.864 190.08 ;
    END
  END f_d[270]
  PIN f_d[271]
    DIRECTION INPUT ;
    USE SIGNAL ;
    PORT
      LAYER M5 ;
        RECT  94.128 189.996 94.152 190.08 ;
    END
  END f_d[271]
  PIN f_d[272]
    DIRECTION INPUT ;
    USE SIGNAL ;
    PORT
      LAYER M5 ;
        RECT  94.464 189.996 94.488 190.08 ;
    END
  END f_d[272]
  PIN f_d[273]
    DIRECTION INPUT ;
    USE SIGNAL ;
    PORT
      LAYER M5 ;
        RECT  94.752 189.996 94.776 190.08 ;
    END
  END f_d[273]
  PIN f_d[274]
    DIRECTION INPUT ;
    USE SIGNAL ;
    PORT
      LAYER M5 ;
        RECT  95.04 189.996 95.064 190.08 ;
    END
  END f_d[274]
  PIN f_d[275]
    DIRECTION INPUT ;
    USE SIGNAL ;
    PORT
      LAYER M5 ;
        RECT  95.376 189.996 95.4 190.08 ;
    END
  END f_d[275]
  PIN f_d[276]
    DIRECTION INPUT ;
    USE SIGNAL ;
    PORT
      LAYER M5 ;
        RECT  95.664 189.996 95.688 190.08 ;
    END
  END f_d[276]
  PIN f_d[277]
    DIRECTION INPUT ;
    USE SIGNAL ;
    PORT
      LAYER M5 ;
        RECT  95.952 189.996 95.976 190.08 ;
    END
  END f_d[277]
  PIN f_d[278]
    DIRECTION INPUT ;
    USE SIGNAL ;
    PORT
      LAYER M5 ;
        RECT  96.24 189.996 96.264 190.08 ;
    END
  END f_d[278]
  PIN f_d[279]
    DIRECTION INPUT ;
    USE SIGNAL ;
    PORT
      LAYER M5 ;
        RECT  96.576 189.996 96.6 190.08 ;
    END
  END f_d[279]
  PIN f_d[27]
    DIRECTION INPUT ;
    USE SIGNAL ;
    PORT
      LAYER M5 ;
        RECT  20.832 189.996 20.856 190.08 ;
    END
  END f_d[27]
  PIN f_d[280]
    DIRECTION INPUT ;
    USE SIGNAL ;
    PORT
      LAYER M5 ;
        RECT  96.864 189.996 96.888 190.08 ;
    END
  END f_d[280]
  PIN f_d[281]
    DIRECTION INPUT ;
    USE SIGNAL ;
    PORT
      LAYER M5 ;
        RECT  97.152 189.996 97.176 190.08 ;
    END
  END f_d[281]
  PIN f_d[282]
    DIRECTION INPUT ;
    USE SIGNAL ;
    PORT
      LAYER M5 ;
        RECT  97.44 189.996 97.464 190.08 ;
    END
  END f_d[282]
  PIN f_d[283]
    DIRECTION INPUT ;
    USE SIGNAL ;
    PORT
      LAYER M5 ;
        RECT  97.776 189.996 97.8 190.08 ;
    END
  END f_d[283]
  PIN f_d[284]
    DIRECTION INPUT ;
    USE SIGNAL ;
    PORT
      LAYER M5 ;
        RECT  98.064 189.996 98.088 190.08 ;
    END
  END f_d[284]
  PIN f_d[285]
    DIRECTION INPUT ;
    USE SIGNAL ;
    PORT
      LAYER M5 ;
        RECT  98.352 189.996 98.376 190.08 ;
    END
  END f_d[285]
  PIN f_d[286]
    DIRECTION INPUT ;
    USE SIGNAL ;
    PORT
      LAYER M5 ;
        RECT  98.64 189.996 98.664 190.08 ;
    END
  END f_d[286]
  PIN f_d[287]
    DIRECTION INPUT ;
    USE SIGNAL ;
    PORT
      LAYER M5 ;
        RECT  98.976 189.996 99 190.08 ;
    END
  END f_d[287]
  PIN f_d[288]
    DIRECTION INPUT ;
    USE SIGNAL ;
    PORT
      LAYER M5 ;
        RECT  99.264 189.996 99.288 190.08 ;
    END
  END f_d[288]
  PIN f_d[289]
    DIRECTION INPUT ;
    USE SIGNAL ;
    PORT
      LAYER M5 ;
        RECT  99.552 189.996 99.576 190.08 ;
    END
  END f_d[289]
  PIN f_d[28]
    DIRECTION INPUT ;
    USE SIGNAL ;
    PORT
      LAYER M5 ;
        RECT  21.168 189.996 21.192 190.08 ;
    END
  END f_d[28]
  PIN f_d[290]
    DIRECTION INPUT ;
    USE SIGNAL ;
    PORT
      LAYER M5 ;
        RECT  99.84 189.996 99.864 190.08 ;
    END
  END f_d[290]
  PIN f_d[291]
    DIRECTION INPUT ;
    USE SIGNAL ;
    PORT
      LAYER M5 ;
        RECT  100.176 189.996 100.2 190.08 ;
    END
  END f_d[291]
  PIN f_d[292]
    DIRECTION INPUT ;
    USE SIGNAL ;
    PORT
      LAYER M5 ;
        RECT  100.464 189.996 100.488 190.08 ;
    END
  END f_d[292]
  PIN f_d[293]
    DIRECTION INPUT ;
    USE SIGNAL ;
    PORT
      LAYER M5 ;
        RECT  100.752 189.996 100.776 190.08 ;
    END
  END f_d[293]
  PIN f_d[294]
    DIRECTION INPUT ;
    USE SIGNAL ;
    PORT
      LAYER M5 ;
        RECT  101.04 189.996 101.064 190.08 ;
    END
  END f_d[294]
  PIN f_d[295]
    DIRECTION INPUT ;
    USE SIGNAL ;
    PORT
      LAYER M5 ;
        RECT  101.376 189.996 101.4 190.08 ;
    END
  END f_d[295]
  PIN f_d[296]
    DIRECTION INPUT ;
    USE SIGNAL ;
    PORT
      LAYER M5 ;
        RECT  101.664 189.996 101.688 190.08 ;
    END
  END f_d[296]
  PIN f_d[297]
    DIRECTION INPUT ;
    USE SIGNAL ;
    PORT
      LAYER M5 ;
        RECT  101.952 189.996 101.976 190.08 ;
    END
  END f_d[297]
  PIN f_d[298]
    DIRECTION INPUT ;
    USE SIGNAL ;
    PORT
      LAYER M5 ;
        RECT  102.24 189.996 102.264 190.08 ;
    END
  END f_d[298]
  PIN f_d[299]
    DIRECTION INPUT ;
    USE SIGNAL ;
    PORT
      LAYER M5 ;
        RECT  102.576 189.996 102.6 190.08 ;
    END
  END f_d[299]
  PIN f_d[29]
    DIRECTION INPUT ;
    USE SIGNAL ;
    PORT
      LAYER M5 ;
        RECT  21.456 189.996 21.48 190.08 ;
    END
  END f_d[29]
  PIN f_d[2]
    DIRECTION INPUT ;
    USE SIGNAL ;
    PORT
      LAYER M5 ;
        RECT  13.344 189.996 13.368 190.08 ;
    END
  END f_d[2]
  PIN f_d[300]
    DIRECTION INPUT ;
    USE SIGNAL ;
    PORT
      LAYER M5 ;
        RECT  102.864 189.996 102.888 190.08 ;
    END
  END f_d[300]
  PIN f_d[301]
    DIRECTION INPUT ;
    USE SIGNAL ;
    PORT
      LAYER M5 ;
        RECT  103.152 189.996 103.176 190.08 ;
    END
  END f_d[301]
  PIN f_d[302]
    DIRECTION INPUT ;
    USE SIGNAL ;
    PORT
      LAYER M5 ;
        RECT  103.488 189.996 103.512 190.08 ;
    END
  END f_d[302]
  PIN f_d[303]
    DIRECTION INPUT ;
    USE SIGNAL ;
    PORT
      LAYER M5 ;
        RECT  103.776 189.996 103.8 190.08 ;
    END
  END f_d[303]
  PIN f_d[304]
    DIRECTION INPUT ;
    USE SIGNAL ;
    PORT
      LAYER M5 ;
        RECT  104.064 189.996 104.088 190.08 ;
    END
  END f_d[304]
  PIN f_d[305]
    DIRECTION INPUT ;
    USE SIGNAL ;
    PORT
      LAYER M5 ;
        RECT  104.352 189.996 104.376 190.08 ;
    END
  END f_d[305]
  PIN f_d[306]
    DIRECTION INPUT ;
    USE SIGNAL ;
    PORT
      LAYER M5 ;
        RECT  104.688 189.996 104.712 190.08 ;
    END
  END f_d[306]
  PIN f_d[307]
    DIRECTION INPUT ;
    USE SIGNAL ;
    PORT
      LAYER M5 ;
        RECT  104.976 189.996 105 190.08 ;
    END
  END f_d[307]
  PIN f_d[308]
    DIRECTION INPUT ;
    USE SIGNAL ;
    PORT
      LAYER M5 ;
        RECT  105.264 189.996 105.288 190.08 ;
    END
  END f_d[308]
  PIN f_d[309]
    DIRECTION INPUT ;
    USE SIGNAL ;
    PORT
      LAYER M5 ;
        RECT  105.552 189.996 105.576 190.08 ;
    END
  END f_d[309]
  PIN f_d[30]
    DIRECTION INPUT ;
    USE SIGNAL ;
    PORT
      LAYER M5 ;
        RECT  21.744 189.996 21.768 190.08 ;
    END
  END f_d[30]
  PIN f_d[310]
    DIRECTION INPUT ;
    USE SIGNAL ;
    PORT
      LAYER M5 ;
        RECT  105.888 189.996 105.912 190.08 ;
    END
  END f_d[310]
  PIN f_d[311]
    DIRECTION INPUT ;
    USE SIGNAL ;
    PORT
      LAYER M5 ;
        RECT  106.176 189.996 106.2 190.08 ;
    END
  END f_d[311]
  PIN f_d[312]
    DIRECTION INPUT ;
    USE SIGNAL ;
    PORT
      LAYER M5 ;
        RECT  106.464 189.996 106.488 190.08 ;
    END
  END f_d[312]
  PIN f_d[313]
    DIRECTION INPUT ;
    USE SIGNAL ;
    PORT
      LAYER M5 ;
        RECT  106.752 189.996 106.776 190.08 ;
    END
  END f_d[313]
  PIN f_d[314]
    DIRECTION INPUT ;
    USE SIGNAL ;
    PORT
      LAYER M5 ;
        RECT  107.088 189.996 107.112 190.08 ;
    END
  END f_d[314]
  PIN f_d[315]
    DIRECTION INPUT ;
    USE SIGNAL ;
    PORT
      LAYER M5 ;
        RECT  107.376 189.996 107.4 190.08 ;
    END
  END f_d[315]
  PIN f_d[316]
    DIRECTION INPUT ;
    USE SIGNAL ;
    PORT
      LAYER M5 ;
        RECT  107.664 189.996 107.688 190.08 ;
    END
  END f_d[316]
  PIN f_d[317]
    DIRECTION INPUT ;
    USE SIGNAL ;
    PORT
      LAYER M5 ;
        RECT  107.952 189.996 107.976 190.08 ;
    END
  END f_d[317]
  PIN f_d[318]
    DIRECTION INPUT ;
    USE SIGNAL ;
    PORT
      LAYER M5 ;
        RECT  108.288 189.996 108.312 190.08 ;
    END
  END f_d[318]
  PIN f_d[319]
    DIRECTION INPUT ;
    USE SIGNAL ;
    PORT
      LAYER M5 ;
        RECT  108.576 189.996 108.6 190.08 ;
    END
  END f_d[319]
  PIN f_d[31]
    DIRECTION INPUT ;
    USE SIGNAL ;
    PORT
      LAYER M5 ;
        RECT  22.032 189.996 22.056 190.08 ;
    END
  END f_d[31]
  PIN f_d[320]
    DIRECTION INPUT ;
    USE SIGNAL ;
    PORT
      LAYER M5 ;
        RECT  108.864 189.996 108.888 190.08 ;
    END
  END f_d[320]
  PIN f_d[321]
    DIRECTION INPUT ;
    USE SIGNAL ;
    PORT
      LAYER M5 ;
        RECT  109.152 189.996 109.176 190.08 ;
    END
  END f_d[321]
  PIN f_d[322]
    DIRECTION INPUT ;
    USE SIGNAL ;
    PORT
      LAYER M5 ;
        RECT  109.488 189.996 109.512 190.08 ;
    END
  END f_d[322]
  PIN f_d[323]
    DIRECTION INPUT ;
    USE SIGNAL ;
    PORT
      LAYER M5 ;
        RECT  109.776 189.996 109.8 190.08 ;
    END
  END f_d[323]
  PIN f_d[324]
    DIRECTION INPUT ;
    USE SIGNAL ;
    PORT
      LAYER M5 ;
        RECT  110.064 189.996 110.088 190.08 ;
    END
  END f_d[324]
  PIN f_d[325]
    DIRECTION INPUT ;
    USE SIGNAL ;
    PORT
      LAYER M5 ;
        RECT  110.352 189.996 110.376 190.08 ;
    END
  END f_d[325]
  PIN f_d[326]
    DIRECTION INPUT ;
    USE SIGNAL ;
    PORT
      LAYER M5 ;
        RECT  110.688 189.996 110.712 190.08 ;
    END
  END f_d[326]
  PIN f_d[327]
    DIRECTION INPUT ;
    USE SIGNAL ;
    PORT
      LAYER M5 ;
        RECT  110.976 189.996 111 190.08 ;
    END
  END f_d[327]
  PIN f_d[328]
    DIRECTION INPUT ;
    USE SIGNAL ;
    PORT
      LAYER M5 ;
        RECT  111.264 189.996 111.288 190.08 ;
    END
  END f_d[328]
  PIN f_d[329]
    DIRECTION INPUT ;
    USE SIGNAL ;
    PORT
      LAYER M5 ;
        RECT  111.6 189.996 111.624 190.08 ;
    END
  END f_d[329]
  PIN f_d[32]
    DIRECTION INPUT ;
    USE SIGNAL ;
    PORT
      LAYER M5 ;
        RECT  22.368 189.996 22.392 190.08 ;
    END
  END f_d[32]
  PIN f_d[330]
    DIRECTION INPUT ;
    USE SIGNAL ;
    PORT
      LAYER M5 ;
        RECT  111.888 189.996 111.912 190.08 ;
    END
  END f_d[330]
  PIN f_d[331]
    DIRECTION INPUT ;
    USE SIGNAL ;
    PORT
      LAYER M5 ;
        RECT  112.176 189.996 112.2 190.08 ;
    END
  END f_d[331]
  PIN f_d[332]
    DIRECTION INPUT ;
    USE SIGNAL ;
    PORT
      LAYER M5 ;
        RECT  112.464 189.996 112.488 190.08 ;
    END
  END f_d[332]
  PIN f_d[333]
    DIRECTION INPUT ;
    USE SIGNAL ;
    PORT
      LAYER M5 ;
        RECT  112.8 189.996 112.824 190.08 ;
    END
  END f_d[333]
  PIN f_d[334]
    DIRECTION INPUT ;
    USE SIGNAL ;
    PORT
      LAYER M5 ;
        RECT  113.088 189.996 113.112 190.08 ;
    END
  END f_d[334]
  PIN f_d[335]
    DIRECTION INPUT ;
    USE SIGNAL ;
    PORT
      LAYER M5 ;
        RECT  113.376 189.996 113.4 190.08 ;
    END
  END f_d[335]
  PIN f_d[336]
    DIRECTION INPUT ;
    USE SIGNAL ;
    PORT
      LAYER M5 ;
        RECT  113.664 189.996 113.688 190.08 ;
    END
  END f_d[336]
  PIN f_d[337]
    DIRECTION INPUT ;
    USE SIGNAL ;
    PORT
      LAYER M5 ;
        RECT  114 189.996 114.024 190.08 ;
    END
  END f_d[337]
  PIN f_d[338]
    DIRECTION INPUT ;
    USE SIGNAL ;
    PORT
      LAYER M5 ;
        RECT  114.288 189.996 114.312 190.08 ;
    END
  END f_d[338]
  PIN f_d[339]
    DIRECTION INPUT ;
    USE SIGNAL ;
    PORT
      LAYER M5 ;
        RECT  114.576 189.996 114.6 190.08 ;
    END
  END f_d[339]
  PIN f_d[33]
    DIRECTION INPUT ;
    USE SIGNAL ;
    PORT
      LAYER M5 ;
        RECT  22.656 189.996 22.68 190.08 ;
    END
  END f_d[33]
  PIN f_d[340]
    DIRECTION INPUT ;
    USE SIGNAL ;
    PORT
      LAYER M5 ;
        RECT  114.864 189.996 114.888 190.08 ;
    END
  END f_d[340]
  PIN f_d[341]
    DIRECTION INPUT ;
    USE SIGNAL ;
    PORT
      LAYER M5 ;
        RECT  115.2 189.996 115.224 190.08 ;
    END
  END f_d[341]
  PIN f_d[342]
    DIRECTION INPUT ;
    USE SIGNAL ;
    PORT
      LAYER M5 ;
        RECT  115.488 189.996 115.512 190.08 ;
    END
  END f_d[342]
  PIN f_d[343]
    DIRECTION INPUT ;
    USE SIGNAL ;
    PORT
      LAYER M5 ;
        RECT  115.776 189.996 115.8 190.08 ;
    END
  END f_d[343]
  PIN f_d[344]
    DIRECTION INPUT ;
    USE SIGNAL ;
    PORT
      LAYER M5 ;
        RECT  116.064 189.996 116.088 190.08 ;
    END
  END f_d[344]
  PIN f_d[345]
    DIRECTION INPUT ;
    USE SIGNAL ;
    PORT
      LAYER M5 ;
        RECT  116.4 189.996 116.424 190.08 ;
    END
  END f_d[345]
  PIN f_d[346]
    DIRECTION INPUT ;
    USE SIGNAL ;
    PORT
      LAYER M5 ;
        RECT  116.688 189.996 116.712 190.08 ;
    END
  END f_d[346]
  PIN f_d[347]
    DIRECTION INPUT ;
    USE SIGNAL ;
    PORT
      LAYER M5 ;
        RECT  116.976 189.996 117 190.08 ;
    END
  END f_d[347]
  PIN f_d[348]
    DIRECTION INPUT ;
    USE SIGNAL ;
    PORT
      LAYER M5 ;
        RECT  117.264 189.996 117.288 190.08 ;
    END
  END f_d[348]
  PIN f_d[349]
    DIRECTION INPUT ;
    USE SIGNAL ;
    PORT
      LAYER M5 ;
        RECT  117.6 189.996 117.624 190.08 ;
    END
  END f_d[349]
  PIN f_d[34]
    DIRECTION INPUT ;
    USE SIGNAL ;
    PORT
      LAYER M5 ;
        RECT  22.944 189.996 22.968 190.08 ;
    END
  END f_d[34]
  PIN f_d[350]
    DIRECTION INPUT ;
    USE SIGNAL ;
    PORT
      LAYER M5 ;
        RECT  117.888 189.996 117.912 190.08 ;
    END
  END f_d[350]
  PIN f_d[351]
    DIRECTION INPUT ;
    USE SIGNAL ;
    PORT
      LAYER M5 ;
        RECT  118.176 189.996 118.2 190.08 ;
    END
  END f_d[351]
  PIN f_d[352]
    DIRECTION INPUT ;
    USE SIGNAL ;
    PORT
      LAYER M5 ;
        RECT  118.464 189.996 118.488 190.08 ;
    END
  END f_d[352]
  PIN f_d[353]
    DIRECTION INPUT ;
    USE SIGNAL ;
    PORT
      LAYER M5 ;
        RECT  118.8 189.996 118.824 190.08 ;
    END
  END f_d[353]
  PIN f_d[354]
    DIRECTION INPUT ;
    USE SIGNAL ;
    PORT
      LAYER M5 ;
        RECT  119.088 189.996 119.112 190.08 ;
    END
  END f_d[354]
  PIN f_d[355]
    DIRECTION INPUT ;
    USE SIGNAL ;
    PORT
      LAYER M5 ;
        RECT  119.376 189.996 119.4 190.08 ;
    END
  END f_d[355]
  PIN f_d[356]
    DIRECTION INPUT ;
    USE SIGNAL ;
    PORT
      LAYER M5 ;
        RECT  119.712 189.996 119.736 190.08 ;
    END
  END f_d[356]
  PIN f_d[357]
    DIRECTION INPUT ;
    USE SIGNAL ;
    PORT
      LAYER M5 ;
        RECT  120 189.996 120.024 190.08 ;
    END
  END f_d[357]
  PIN f_d[358]
    DIRECTION INPUT ;
    USE SIGNAL ;
    PORT
      LAYER M5 ;
        RECT  120.288 189.996 120.312 190.08 ;
    END
  END f_d[358]
  PIN f_d[359]
    DIRECTION INPUT ;
    USE SIGNAL ;
    PORT
      LAYER M5 ;
        RECT  120.576 189.996 120.6 190.08 ;
    END
  END f_d[359]
  PIN f_d[35]
    DIRECTION INPUT ;
    USE SIGNAL ;
    PORT
      LAYER M5 ;
        RECT  23.232 189.996 23.256 190.08 ;
    END
  END f_d[35]
  PIN f_d[360]
    DIRECTION INPUT ;
    USE SIGNAL ;
    PORT
      LAYER M5 ;
        RECT  120.912 189.996 120.936 190.08 ;
    END
  END f_d[360]
  PIN f_d[361]
    DIRECTION INPUT ;
    USE SIGNAL ;
    PORT
      LAYER M5 ;
        RECT  121.2 189.996 121.224 190.08 ;
    END
  END f_d[361]
  PIN f_d[362]
    DIRECTION INPUT ;
    USE SIGNAL ;
    PORT
      LAYER M5 ;
        RECT  121.488 189.996 121.512 190.08 ;
    END
  END f_d[362]
  PIN f_d[363]
    DIRECTION INPUT ;
    USE SIGNAL ;
    PORT
      LAYER M5 ;
        RECT  121.776 189.996 121.8 190.08 ;
    END
  END f_d[363]
  PIN f_d[364]
    DIRECTION INPUT ;
    USE SIGNAL ;
    PORT
      LAYER M5 ;
        RECT  122.112 189.996 122.136 190.08 ;
    END
  END f_d[364]
  PIN f_d[365]
    DIRECTION INPUT ;
    USE SIGNAL ;
    PORT
      LAYER M5 ;
        RECT  122.4 189.996 122.424 190.08 ;
    END
  END f_d[365]
  PIN f_d[366]
    DIRECTION INPUT ;
    USE SIGNAL ;
    PORT
      LAYER M5 ;
        RECT  122.688 189.996 122.712 190.08 ;
    END
  END f_d[366]
  PIN f_d[367]
    DIRECTION INPUT ;
    USE SIGNAL ;
    PORT
      LAYER M5 ;
        RECT  122.976 189.996 123 190.08 ;
    END
  END f_d[367]
  PIN f_d[368]
    DIRECTION INPUT ;
    USE SIGNAL ;
    PORT
      LAYER M5 ;
        RECT  123.312 189.996 123.336 190.08 ;
    END
  END f_d[368]
  PIN f_d[369]
    DIRECTION INPUT ;
    USE SIGNAL ;
    PORT
      LAYER M5 ;
        RECT  123.6 189.996 123.624 190.08 ;
    END
  END f_d[369]
  PIN f_d[36]
    DIRECTION INPUT ;
    USE SIGNAL ;
    PORT
      LAYER M5 ;
        RECT  23.568 189.996 23.592 190.08 ;
    END
  END f_d[36]
  PIN f_d[370]
    DIRECTION INPUT ;
    USE SIGNAL ;
    PORT
      LAYER M5 ;
        RECT  123.888 189.996 123.912 190.08 ;
    END
  END f_d[370]
  PIN f_d[371]
    DIRECTION INPUT ;
    USE SIGNAL ;
    PORT
      LAYER M5 ;
        RECT  124.176 189.996 124.2 190.08 ;
    END
  END f_d[371]
  PIN f_d[372]
    DIRECTION INPUT ;
    USE SIGNAL ;
    PORT
      LAYER M5 ;
        RECT  124.512 189.996 124.536 190.08 ;
    END
  END f_d[372]
  PIN f_d[373]
    DIRECTION INPUT ;
    USE SIGNAL ;
    PORT
      LAYER M5 ;
        RECT  124.8 189.996 124.824 190.08 ;
    END
  END f_d[373]
  PIN f_d[374]
    DIRECTION INPUT ;
    USE SIGNAL ;
    PORT
      LAYER M5 ;
        RECT  125.088 189.996 125.112 190.08 ;
    END
  END f_d[374]
  PIN f_d[375]
    DIRECTION INPUT ;
    USE SIGNAL ;
    PORT
      LAYER M5 ;
        RECT  125.376 189.996 125.4 190.08 ;
    END
  END f_d[375]
  PIN f_d[376]
    DIRECTION INPUT ;
    USE SIGNAL ;
    PORT
      LAYER M5 ;
        RECT  125.712 189.996 125.736 190.08 ;
    END
  END f_d[376]
  PIN f_d[377]
    DIRECTION INPUT ;
    USE SIGNAL ;
    PORT
      LAYER M5 ;
        RECT  126 189.996 126.024 190.08 ;
    END
  END f_d[377]
  PIN f_d[378]
    DIRECTION INPUT ;
    USE SIGNAL ;
    PORT
      LAYER M5 ;
        RECT  126.288 189.996 126.312 190.08 ;
    END
  END f_d[378]
  PIN f_d[379]
    DIRECTION INPUT ;
    USE SIGNAL ;
    PORT
      LAYER M5 ;
        RECT  126.576 189.996 126.6 190.08 ;
    END
  END f_d[379]
  PIN f_d[37]
    DIRECTION INPUT ;
    USE SIGNAL ;
    PORT
      LAYER M5 ;
        RECT  23.856 189.996 23.88 190.08 ;
    END
  END f_d[37]
  PIN f_d[380]
    DIRECTION INPUT ;
    USE SIGNAL ;
    PORT
      LAYER M5 ;
        RECT  126.912 189.996 126.936 190.08 ;
    END
  END f_d[380]
  PIN f_d[381]
    DIRECTION INPUT ;
    USE SIGNAL ;
    PORT
      LAYER M5 ;
        RECT  127.2 189.996 127.224 190.08 ;
    END
  END f_d[381]
  PIN f_d[382]
    DIRECTION INPUT ;
    USE SIGNAL ;
    PORT
      LAYER M5 ;
        RECT  127.488 189.996 127.512 190.08 ;
    END
  END f_d[382]
  PIN f_d[383]
    DIRECTION INPUT ;
    USE SIGNAL ;
    PORT
      LAYER M5 ;
        RECT  127.824 189.996 127.848 190.08 ;
    END
  END f_d[383]
  PIN f_d[384]
    DIRECTION INPUT ;
    USE SIGNAL ;
    PORT
      LAYER M5 ;
        RECT  128.112 189.996 128.136 190.08 ;
    END
  END f_d[384]
  PIN f_d[385]
    DIRECTION INPUT ;
    USE SIGNAL ;
    PORT
      LAYER M5 ;
        RECT  128.4 189.996 128.424 190.08 ;
    END
  END f_d[385]
  PIN f_d[386]
    DIRECTION INPUT ;
    USE SIGNAL ;
    PORT
      LAYER M5 ;
        RECT  128.688 189.996 128.712 190.08 ;
    END
  END f_d[386]
  PIN f_d[387]
    DIRECTION INPUT ;
    USE SIGNAL ;
    PORT
      LAYER M5 ;
        RECT  129.024 189.996 129.048 190.08 ;
    END
  END f_d[387]
  PIN f_d[388]
    DIRECTION INPUT ;
    USE SIGNAL ;
    PORT
      LAYER M5 ;
        RECT  129.312 189.996 129.336 190.08 ;
    END
  END f_d[388]
  PIN f_d[389]
    DIRECTION INPUT ;
    USE SIGNAL ;
    PORT
      LAYER M5 ;
        RECT  129.6 189.996 129.624 190.08 ;
    END
  END f_d[389]
  PIN f_d[38]
    DIRECTION INPUT ;
    USE SIGNAL ;
    PORT
      LAYER M5 ;
        RECT  24.144 189.996 24.168 190.08 ;
    END
  END f_d[38]
  PIN f_d[390]
    DIRECTION INPUT ;
    USE SIGNAL ;
    PORT
      LAYER M5 ;
        RECT  129.888 189.996 129.912 190.08 ;
    END
  END f_d[390]
  PIN f_d[391]
    DIRECTION INPUT ;
    USE SIGNAL ;
    PORT
      LAYER M5 ;
        RECT  130.224 189.996 130.248 190.08 ;
    END
  END f_d[391]
  PIN f_d[392]
    DIRECTION INPUT ;
    USE SIGNAL ;
    PORT
      LAYER M5 ;
        RECT  130.512 189.996 130.536 190.08 ;
    END
  END f_d[392]
  PIN f_d[393]
    DIRECTION INPUT ;
    USE SIGNAL ;
    PORT
      LAYER M5 ;
        RECT  130.8 189.996 130.824 190.08 ;
    END
  END f_d[393]
  PIN f_d[394]
    DIRECTION INPUT ;
    USE SIGNAL ;
    PORT
      LAYER M5 ;
        RECT  131.088 189.996 131.112 190.08 ;
    END
  END f_d[394]
  PIN f_d[395]
    DIRECTION INPUT ;
    USE SIGNAL ;
    PORT
      LAYER M5 ;
        RECT  131.424 189.996 131.448 190.08 ;
    END
  END f_d[395]
  PIN f_d[396]
    DIRECTION INPUT ;
    USE SIGNAL ;
    PORT
      LAYER M5 ;
        RECT  131.712 189.996 131.736 190.08 ;
    END
  END f_d[396]
  PIN f_d[397]
    DIRECTION INPUT ;
    USE SIGNAL ;
    PORT
      LAYER M5 ;
        RECT  132 189.996 132.024 190.08 ;
    END
  END f_d[397]
  PIN f_d[398]
    DIRECTION INPUT ;
    USE SIGNAL ;
    PORT
      LAYER M5 ;
        RECT  132.288 189.996 132.312 190.08 ;
    END
  END f_d[398]
  PIN f_d[399]
    DIRECTION INPUT ;
    USE SIGNAL ;
    PORT
      LAYER M5 ;
        RECT  132.624 189.996 132.648 190.08 ;
    END
  END f_d[399]
  PIN f_d[39]
    DIRECTION INPUT ;
    USE SIGNAL ;
    PORT
      LAYER M5 ;
        RECT  24.432 189.996 24.456 190.08 ;
    END
  END f_d[39]
  PIN f_d[3]
    DIRECTION INPUT ;
    USE SIGNAL ;
    PORT
      LAYER M5 ;
        RECT  13.632 189.996 13.656 190.08 ;
    END
  END f_d[3]
  PIN f_d[400]
    DIRECTION INPUT ;
    USE SIGNAL ;
    PORT
      LAYER M5 ;
        RECT  132.912 189.996 132.936 190.08 ;
    END
  END f_d[400]
  PIN f_d[401]
    DIRECTION INPUT ;
    USE SIGNAL ;
    PORT
      LAYER M5 ;
        RECT  133.2 189.996 133.224 190.08 ;
    END
  END f_d[401]
  PIN f_d[402]
    DIRECTION INPUT ;
    USE SIGNAL ;
    PORT
      LAYER M5 ;
        RECT  133.488 189.996 133.512 190.08 ;
    END
  END f_d[402]
  PIN f_d[403]
    DIRECTION INPUT ;
    USE SIGNAL ;
    PORT
      LAYER M5 ;
        RECT  133.824 189.996 133.848 190.08 ;
    END
  END f_d[403]
  PIN f_d[404]
    DIRECTION INPUT ;
    USE SIGNAL ;
    PORT
      LAYER M5 ;
        RECT  134.112 189.996 134.136 190.08 ;
    END
  END f_d[404]
  PIN f_d[405]
    DIRECTION INPUT ;
    USE SIGNAL ;
    PORT
      LAYER M5 ;
        RECT  134.4 189.996 134.424 190.08 ;
    END
  END f_d[405]
  PIN f_d[406]
    DIRECTION INPUT ;
    USE SIGNAL ;
    PORT
      LAYER M5 ;
        RECT  134.688 189.996 134.712 190.08 ;
    END
  END f_d[406]
  PIN f_d[407]
    DIRECTION INPUT ;
    USE SIGNAL ;
    PORT
      LAYER M5 ;
        RECT  135.024 189.996 135.048 190.08 ;
    END
  END f_d[407]
  PIN f_d[408]
    DIRECTION INPUT ;
    USE SIGNAL ;
    PORT
      LAYER M5 ;
        RECT  135.312 189.996 135.336 190.08 ;
    END
  END f_d[408]
  PIN f_d[409]
    DIRECTION INPUT ;
    USE SIGNAL ;
    PORT
      LAYER M5 ;
        RECT  135.6 189.996 135.624 190.08 ;
    END
  END f_d[409]
  PIN f_d[40]
    DIRECTION INPUT ;
    USE SIGNAL ;
    PORT
      LAYER M5 ;
        RECT  24.768 189.996 24.792 190.08 ;
    END
  END f_d[40]
  PIN f_d[410]
    DIRECTION INPUT ;
    USE SIGNAL ;
    PORT
      LAYER M5 ;
        RECT  135.888 189.996 135.912 190.08 ;
    END
  END f_d[410]
  PIN f_d[411]
    DIRECTION INPUT ;
    USE SIGNAL ;
    PORT
      LAYER M5 ;
        RECT  136.224 189.996 136.248 190.08 ;
    END
  END f_d[411]
  PIN f_d[412]
    DIRECTION INPUT ;
    USE SIGNAL ;
    PORT
      LAYER M5 ;
        RECT  136.512 189.996 136.536 190.08 ;
    END
  END f_d[412]
  PIN f_d[413]
    DIRECTION INPUT ;
    USE SIGNAL ;
    PORT
      LAYER M5 ;
        RECT  136.8 189.996 136.824 190.08 ;
    END
  END f_d[413]
  PIN f_d[414]
    DIRECTION INPUT ;
    USE SIGNAL ;
    PORT
      LAYER M5 ;
        RECT  137.136 189.996 137.16 190.08 ;
    END
  END f_d[414]
  PIN f_d[415]
    DIRECTION INPUT ;
    USE SIGNAL ;
    PORT
      LAYER M5 ;
        RECT  137.424 189.996 137.448 190.08 ;
    END
  END f_d[415]
  PIN f_d[416]
    DIRECTION INPUT ;
    USE SIGNAL ;
    PORT
      LAYER M5 ;
        RECT  137.712 189.996 137.736 190.08 ;
    END
  END f_d[416]
  PIN f_d[417]
    DIRECTION INPUT ;
    USE SIGNAL ;
    PORT
      LAYER M5 ;
        RECT  138 189.996 138.024 190.08 ;
    END
  END f_d[417]
  PIN f_d[418]
    DIRECTION INPUT ;
    USE SIGNAL ;
    PORT
      LAYER M5 ;
        RECT  138.336 189.996 138.36 190.08 ;
    END
  END f_d[418]
  PIN f_d[419]
    DIRECTION INPUT ;
    USE SIGNAL ;
    PORT
      LAYER M5 ;
        RECT  138.624 189.996 138.648 190.08 ;
    END
  END f_d[419]
  PIN f_d[41]
    DIRECTION INPUT ;
    USE SIGNAL ;
    PORT
      LAYER M5 ;
        RECT  25.056 189.996 25.08 190.08 ;
    END
  END f_d[41]
  PIN f_d[420]
    DIRECTION INPUT ;
    USE SIGNAL ;
    PORT
      LAYER M5 ;
        RECT  138.912 189.996 138.936 190.08 ;
    END
  END f_d[420]
  PIN f_d[421]
    DIRECTION INPUT ;
    USE SIGNAL ;
    PORT
      LAYER M5 ;
        RECT  139.2 189.996 139.224 190.08 ;
    END
  END f_d[421]
  PIN f_d[422]
    DIRECTION INPUT ;
    USE SIGNAL ;
    PORT
      LAYER M5 ;
        RECT  139.536 189.996 139.56 190.08 ;
    END
  END f_d[422]
  PIN f_d[423]
    DIRECTION INPUT ;
    USE SIGNAL ;
    PORT
      LAYER M5 ;
        RECT  139.824 189.996 139.848 190.08 ;
    END
  END f_d[423]
  PIN f_d[424]
    DIRECTION INPUT ;
    USE SIGNAL ;
    PORT
      LAYER M5 ;
        RECT  140.112 189.996 140.136 190.08 ;
    END
  END f_d[424]
  PIN f_d[425]
    DIRECTION INPUT ;
    USE SIGNAL ;
    PORT
      LAYER M5 ;
        RECT  140.4 189.996 140.424 190.08 ;
    END
  END f_d[425]
  PIN f_d[426]
    DIRECTION INPUT ;
    USE SIGNAL ;
    PORT
      LAYER M5 ;
        RECT  140.736 189.996 140.76 190.08 ;
    END
  END f_d[426]
  PIN f_d[427]
    DIRECTION INPUT ;
    USE SIGNAL ;
    PORT
      LAYER M5 ;
        RECT  141.024 189.996 141.048 190.08 ;
    END
  END f_d[427]
  PIN f_d[428]
    DIRECTION INPUT ;
    USE SIGNAL ;
    PORT
      LAYER M5 ;
        RECT  141.312 189.996 141.336 190.08 ;
    END
  END f_d[428]
  PIN f_d[429]
    DIRECTION INPUT ;
    USE SIGNAL ;
    PORT
      LAYER M5 ;
        RECT  141.6 189.996 141.624 190.08 ;
    END
  END f_d[429]
  PIN f_d[42]
    DIRECTION INPUT ;
    USE SIGNAL ;
    PORT
      LAYER M5 ;
        RECT  25.344 189.996 25.368 190.08 ;
    END
  END f_d[42]
  PIN f_d[430]
    DIRECTION INPUT ;
    USE SIGNAL ;
    PORT
      LAYER M5 ;
        RECT  141.936 189.996 141.96 190.08 ;
    END
  END f_d[430]
  PIN f_d[431]
    DIRECTION INPUT ;
    USE SIGNAL ;
    PORT
      LAYER M5 ;
        RECT  142.224 189.996 142.248 190.08 ;
    END
  END f_d[431]
  PIN f_d[432]
    DIRECTION INPUT ;
    USE SIGNAL ;
    PORT
      LAYER M5 ;
        RECT  142.512 189.996 142.536 190.08 ;
    END
  END f_d[432]
  PIN f_d[433]
    DIRECTION INPUT ;
    USE SIGNAL ;
    PORT
      LAYER M5 ;
        RECT  142.8 189.996 142.824 190.08 ;
    END
  END f_d[433]
  PIN f_d[434]
    DIRECTION INPUT ;
    USE SIGNAL ;
    PORT
      LAYER M5 ;
        RECT  143.136 189.996 143.16 190.08 ;
    END
  END f_d[434]
  PIN f_d[435]
    DIRECTION INPUT ;
    USE SIGNAL ;
    PORT
      LAYER M5 ;
        RECT  143.424 189.996 143.448 190.08 ;
    END
  END f_d[435]
  PIN f_d[436]
    DIRECTION INPUT ;
    USE SIGNAL ;
    PORT
      LAYER M5 ;
        RECT  143.712 189.996 143.736 190.08 ;
    END
  END f_d[436]
  PIN f_d[437]
    DIRECTION INPUT ;
    USE SIGNAL ;
    PORT
      LAYER M5 ;
        RECT  144 189.996 144.024 190.08 ;
    END
  END f_d[437]
  PIN f_d[438]
    DIRECTION INPUT ;
    USE SIGNAL ;
    PORT
      LAYER M5 ;
        RECT  144.336 189.996 144.36 190.08 ;
    END
  END f_d[438]
  PIN f_d[439]
    DIRECTION INPUT ;
    USE SIGNAL ;
    PORT
      LAYER M5 ;
        RECT  144.624 189.996 144.648 190.08 ;
    END
  END f_d[439]
  PIN f_d[43]
    DIRECTION INPUT ;
    USE SIGNAL ;
    PORT
      LAYER M5 ;
        RECT  25.632 189.996 25.656 190.08 ;
    END
  END f_d[43]
  PIN f_d[440]
    DIRECTION INPUT ;
    USE SIGNAL ;
    PORT
      LAYER M5 ;
        RECT  144.912 189.996 144.936 190.08 ;
    END
  END f_d[440]
  PIN f_d[441]
    DIRECTION INPUT ;
    USE SIGNAL ;
    PORT
      LAYER M5 ;
        RECT  145.248 189.996 145.272 190.08 ;
    END
  END f_d[441]
  PIN f_d[442]
    DIRECTION INPUT ;
    USE SIGNAL ;
    PORT
      LAYER M5 ;
        RECT  145.536 189.996 145.56 190.08 ;
    END
  END f_d[442]
  PIN f_d[443]
    DIRECTION INPUT ;
    USE SIGNAL ;
    PORT
      LAYER M5 ;
        RECT  145.824 189.996 145.848 190.08 ;
    END
  END f_d[443]
  PIN f_d[444]
    DIRECTION INPUT ;
    USE SIGNAL ;
    PORT
      LAYER M5 ;
        RECT  146.112 189.996 146.136 190.08 ;
    END
  END f_d[444]
  PIN f_d[445]
    DIRECTION INPUT ;
    USE SIGNAL ;
    PORT
      LAYER M5 ;
        RECT  146.448 189.996 146.472 190.08 ;
    END
  END f_d[445]
  PIN f_d[446]
    DIRECTION INPUT ;
    USE SIGNAL ;
    PORT
      LAYER M5 ;
        RECT  146.736 189.996 146.76 190.08 ;
    END
  END f_d[446]
  PIN f_d[447]
    DIRECTION INPUT ;
    USE SIGNAL ;
    PORT
      LAYER M5 ;
        RECT  147.024 189.996 147.048 190.08 ;
    END
  END f_d[447]
  PIN f_d[448]
    DIRECTION INPUT ;
    USE SIGNAL ;
    PORT
      LAYER M5 ;
        RECT  147.312 189.996 147.336 190.08 ;
    END
  END f_d[448]
  PIN f_d[449]
    DIRECTION INPUT ;
    USE SIGNAL ;
    PORT
      LAYER M5 ;
        RECT  147.648 189.996 147.672 190.08 ;
    END
  END f_d[449]
  PIN f_d[44]
    DIRECTION INPUT ;
    USE SIGNAL ;
    PORT
      LAYER M5 ;
        RECT  25.968 189.996 25.992 190.08 ;
    END
  END f_d[44]
  PIN f_d[450]
    DIRECTION INPUT ;
    USE SIGNAL ;
    PORT
      LAYER M5 ;
        RECT  147.936 189.996 147.96 190.08 ;
    END
  END f_d[450]
  PIN f_d[451]
    DIRECTION INPUT ;
    USE SIGNAL ;
    PORT
      LAYER M5 ;
        RECT  148.224 189.996 148.248 190.08 ;
    END
  END f_d[451]
  PIN f_d[452]
    DIRECTION INPUT ;
    USE SIGNAL ;
    PORT
      LAYER M5 ;
        RECT  148.512 189.996 148.536 190.08 ;
    END
  END f_d[452]
  PIN f_d[453]
    DIRECTION INPUT ;
    USE SIGNAL ;
    PORT
      LAYER M5 ;
        RECT  148.848 189.996 148.872 190.08 ;
    END
  END f_d[453]
  PIN f_d[454]
    DIRECTION INPUT ;
    USE SIGNAL ;
    PORT
      LAYER M5 ;
        RECT  149.136 189.996 149.16 190.08 ;
    END
  END f_d[454]
  PIN f_d[455]
    DIRECTION INPUT ;
    USE SIGNAL ;
    PORT
      LAYER M5 ;
        RECT  149.424 189.996 149.448 190.08 ;
    END
  END f_d[455]
  PIN f_d[456]
    DIRECTION INPUT ;
    USE SIGNAL ;
    PORT
      LAYER M5 ;
        RECT  149.712 189.996 149.736 190.08 ;
    END
  END f_d[456]
  PIN f_d[457]
    DIRECTION INPUT ;
    USE SIGNAL ;
    PORT
      LAYER M5 ;
        RECT  150.048 189.996 150.072 190.08 ;
    END
  END f_d[457]
  PIN f_d[458]
    DIRECTION INPUT ;
    USE SIGNAL ;
    PORT
      LAYER M5 ;
        RECT  150.336 189.996 150.36 190.08 ;
    END
  END f_d[458]
  PIN f_d[459]
    DIRECTION INPUT ;
    USE SIGNAL ;
    PORT
      LAYER M5 ;
        RECT  150.624 189.996 150.648 190.08 ;
    END
  END f_d[459]
  PIN f_d[45]
    DIRECTION INPUT ;
    USE SIGNAL ;
    PORT
      LAYER M5 ;
        RECT  26.256 189.996 26.28 190.08 ;
    END
  END f_d[45]
  PIN f_d[460]
    DIRECTION INPUT ;
    USE SIGNAL ;
    PORT
      LAYER M5 ;
        RECT  150.912 189.996 150.936 190.08 ;
    END
  END f_d[460]
  PIN f_d[461]
    DIRECTION INPUT ;
    USE SIGNAL ;
    PORT
      LAYER M5 ;
        RECT  151.248 189.996 151.272 190.08 ;
    END
  END f_d[461]
  PIN f_d[462]
    DIRECTION INPUT ;
    USE SIGNAL ;
    PORT
      LAYER M5 ;
        RECT  151.536 189.996 151.56 190.08 ;
    END
  END f_d[462]
  PIN f_d[463]
    DIRECTION INPUT ;
    USE SIGNAL ;
    PORT
      LAYER M5 ;
        RECT  151.824 189.996 151.848 190.08 ;
    END
  END f_d[463]
  PIN f_d[464]
    DIRECTION INPUT ;
    USE SIGNAL ;
    PORT
      LAYER M5 ;
        RECT  152.112 189.996 152.136 190.08 ;
    END
  END f_d[464]
  PIN f_d[465]
    DIRECTION INPUT ;
    USE SIGNAL ;
    PORT
      LAYER M5 ;
        RECT  152.448 189.996 152.472 190.08 ;
    END
  END f_d[465]
  PIN f_d[466]
    DIRECTION INPUT ;
    USE SIGNAL ;
    PORT
      LAYER M5 ;
        RECT  152.736 189.996 152.76 190.08 ;
    END
  END f_d[466]
  PIN f_d[467]
    DIRECTION INPUT ;
    USE SIGNAL ;
    PORT
      LAYER M5 ;
        RECT  153.024 189.996 153.048 190.08 ;
    END
  END f_d[467]
  PIN f_d[468]
    DIRECTION INPUT ;
    USE SIGNAL ;
    PORT
      LAYER M5 ;
        RECT  153.36 189.996 153.384 190.08 ;
    END
  END f_d[468]
  PIN f_d[469]
    DIRECTION INPUT ;
    USE SIGNAL ;
    PORT
      LAYER M5 ;
        RECT  153.648 189.996 153.672 190.08 ;
    END
  END f_d[469]
  PIN f_d[46]
    DIRECTION INPUT ;
    USE SIGNAL ;
    PORT
      LAYER M5 ;
        RECT  26.544 189.996 26.568 190.08 ;
    END
  END f_d[46]
  PIN f_d[470]
    DIRECTION INPUT ;
    USE SIGNAL ;
    PORT
      LAYER M5 ;
        RECT  153.936 189.996 153.96 190.08 ;
    END
  END f_d[470]
  PIN f_d[471]
    DIRECTION INPUT ;
    USE SIGNAL ;
    PORT
      LAYER M5 ;
        RECT  154.224 189.996 154.248 190.08 ;
    END
  END f_d[471]
  PIN f_d[472]
    DIRECTION INPUT ;
    USE SIGNAL ;
    PORT
      LAYER M5 ;
        RECT  154.56 189.996 154.584 190.08 ;
    END
  END f_d[472]
  PIN f_d[473]
    DIRECTION INPUT ;
    USE SIGNAL ;
    PORT
      LAYER M5 ;
        RECT  154.848 189.996 154.872 190.08 ;
    END
  END f_d[473]
  PIN f_d[474]
    DIRECTION INPUT ;
    USE SIGNAL ;
    PORT
      LAYER M5 ;
        RECT  155.136 189.996 155.16 190.08 ;
    END
  END f_d[474]
  PIN f_d[475]
    DIRECTION INPUT ;
    USE SIGNAL ;
    PORT
      LAYER M5 ;
        RECT  155.424 189.996 155.448 190.08 ;
    END
  END f_d[475]
  PIN f_d[476]
    DIRECTION INPUT ;
    USE SIGNAL ;
    PORT
      LAYER M5 ;
        RECT  155.76 189.996 155.784 190.08 ;
    END
  END f_d[476]
  PIN f_d[477]
    DIRECTION INPUT ;
    USE SIGNAL ;
    PORT
      LAYER M5 ;
        RECT  156.048 189.996 156.072 190.08 ;
    END
  END f_d[477]
  PIN f_d[478]
    DIRECTION INPUT ;
    USE SIGNAL ;
    PORT
      LAYER M5 ;
        RECT  156.336 189.996 156.36 190.08 ;
    END
  END f_d[478]
  PIN f_d[479]
    DIRECTION INPUT ;
    USE SIGNAL ;
    PORT
      LAYER M5 ;
        RECT  156.624 189.996 156.648 190.08 ;
    END
  END f_d[479]
  PIN f_d[47]
    DIRECTION INPUT ;
    USE SIGNAL ;
    PORT
      LAYER M5 ;
        RECT  26.832 189.996 26.856 190.08 ;
    END
  END f_d[47]
  PIN f_d[48]
    DIRECTION INPUT ;
    USE SIGNAL ;
    PORT
      LAYER M5 ;
        RECT  27.168 189.996 27.192 190.08 ;
    END
  END f_d[48]
  PIN f_d[49]
    DIRECTION INPUT ;
    USE SIGNAL ;
    PORT
      LAYER M5 ;
        RECT  27.456 189.996 27.48 190.08 ;
    END
  END f_d[49]
  PIN f_d[4]
    DIRECTION INPUT ;
    USE SIGNAL ;
    PORT
      LAYER M5 ;
        RECT  13.92 189.996 13.944 190.08 ;
    END
  END f_d[4]
  PIN f_d[50]
    DIRECTION INPUT ;
    USE SIGNAL ;
    PORT
      LAYER M5 ;
        RECT  27.744 189.996 27.768 190.08 ;
    END
  END f_d[50]
  PIN f_d[51]
    DIRECTION INPUT ;
    USE SIGNAL ;
    PORT
      LAYER M5 ;
        RECT  28.032 189.996 28.056 190.08 ;
    END
  END f_d[51]
  PIN f_d[52]
    DIRECTION INPUT ;
    USE SIGNAL ;
    PORT
      LAYER M5 ;
        RECT  28.368 189.996 28.392 190.08 ;
    END
  END f_d[52]
  PIN f_d[53]
    DIRECTION INPUT ;
    USE SIGNAL ;
    PORT
      LAYER M5 ;
        RECT  28.656 189.996 28.68 190.08 ;
    END
  END f_d[53]
  PIN f_d[54]
    DIRECTION INPUT ;
    USE SIGNAL ;
    PORT
      LAYER M5 ;
        RECT  28.944 189.996 28.968 190.08 ;
    END
  END f_d[54]
  PIN f_d[55]
    DIRECTION INPUT ;
    USE SIGNAL ;
    PORT
      LAYER M5 ;
        RECT  29.28 189.996 29.304 190.08 ;
    END
  END f_d[55]
  PIN f_d[56]
    DIRECTION INPUT ;
    USE SIGNAL ;
    PORT
      LAYER M5 ;
        RECT  29.568 189.996 29.592 190.08 ;
    END
  END f_d[56]
  PIN f_d[57]
    DIRECTION INPUT ;
    USE SIGNAL ;
    PORT
      LAYER M5 ;
        RECT  29.856 189.996 29.88 190.08 ;
    END
  END f_d[57]
  PIN f_d[58]
    DIRECTION INPUT ;
    USE SIGNAL ;
    PORT
      LAYER M5 ;
        RECT  30.144 189.996 30.168 190.08 ;
    END
  END f_d[58]
  PIN f_d[59]
    DIRECTION INPUT ;
    USE SIGNAL ;
    PORT
      LAYER M5 ;
        RECT  30.48 189.996 30.504 190.08 ;
    END
  END f_d[59]
  PIN f_d[5]
    DIRECTION INPUT ;
    USE SIGNAL ;
    PORT
      LAYER M5 ;
        RECT  14.256 189.996 14.28 190.08 ;
    END
  END f_d[5]
  PIN f_d[60]
    DIRECTION INPUT ;
    USE SIGNAL ;
    PORT
      LAYER M5 ;
        RECT  30.768 189.996 30.792 190.08 ;
    END
  END f_d[60]
  PIN f_d[61]
    DIRECTION INPUT ;
    USE SIGNAL ;
    PORT
      LAYER M5 ;
        RECT  31.056 189.996 31.08 190.08 ;
    END
  END f_d[61]
  PIN f_d[62]
    DIRECTION INPUT ;
    USE SIGNAL ;
    PORT
      LAYER M5 ;
        RECT  31.344 189.996 31.368 190.08 ;
    END
  END f_d[62]
  PIN f_d[63]
    DIRECTION INPUT ;
    USE SIGNAL ;
    PORT
      LAYER M5 ;
        RECT  31.68 189.996 31.704 190.08 ;
    END
  END f_d[63]
  PIN f_d[64]
    DIRECTION INPUT ;
    USE SIGNAL ;
    PORT
      LAYER M5 ;
        RECT  31.968 189.996 31.992 190.08 ;
    END
  END f_d[64]
  PIN f_d[65]
    DIRECTION INPUT ;
    USE SIGNAL ;
    PORT
      LAYER M5 ;
        RECT  32.256 189.996 32.28 190.08 ;
    END
  END f_d[65]
  PIN f_d[66]
    DIRECTION INPUT ;
    USE SIGNAL ;
    PORT
      LAYER M5 ;
        RECT  32.544 189.996 32.568 190.08 ;
    END
  END f_d[66]
  PIN f_d[67]
    DIRECTION INPUT ;
    USE SIGNAL ;
    PORT
      LAYER M5 ;
        RECT  32.88 189.996 32.904 190.08 ;
    END
  END f_d[67]
  PIN f_d[68]
    DIRECTION INPUT ;
    USE SIGNAL ;
    PORT
      LAYER M5 ;
        RECT  33.168 189.996 33.192 190.08 ;
    END
  END f_d[68]
  PIN f_d[69]
    DIRECTION INPUT ;
    USE SIGNAL ;
    PORT
      LAYER M5 ;
        RECT  33.456 189.996 33.48 190.08 ;
    END
  END f_d[69]
  PIN f_d[6]
    DIRECTION INPUT ;
    USE SIGNAL ;
    PORT
      LAYER M5 ;
        RECT  14.544 189.996 14.568 190.08 ;
    END
  END f_d[6]
  PIN f_d[70]
    DIRECTION INPUT ;
    USE SIGNAL ;
    PORT
      LAYER M5 ;
        RECT  33.744 189.996 33.768 190.08 ;
    END
  END f_d[70]
  PIN f_d[71]
    DIRECTION INPUT ;
    USE SIGNAL ;
    PORT
      LAYER M5 ;
        RECT  34.08 189.996 34.104 190.08 ;
    END
  END f_d[71]
  PIN f_d[72]
    DIRECTION INPUT ;
    USE SIGNAL ;
    PORT
      LAYER M5 ;
        RECT  34.368 189.996 34.392 190.08 ;
    END
  END f_d[72]
  PIN f_d[73]
    DIRECTION INPUT ;
    USE SIGNAL ;
    PORT
      LAYER M5 ;
        RECT  34.656 189.996 34.68 190.08 ;
    END
  END f_d[73]
  PIN f_d[74]
    DIRECTION INPUT ;
    USE SIGNAL ;
    PORT
      LAYER M5 ;
        RECT  34.944 189.996 34.968 190.08 ;
    END
  END f_d[74]
  PIN f_d[75]
    DIRECTION INPUT ;
    USE SIGNAL ;
    PORT
      LAYER M5 ;
        RECT  35.28 189.996 35.304 190.08 ;
    END
  END f_d[75]
  PIN f_d[76]
    DIRECTION INPUT ;
    USE SIGNAL ;
    PORT
      LAYER M5 ;
        RECT  35.568 189.996 35.592 190.08 ;
    END
  END f_d[76]
  PIN f_d[77]
    DIRECTION INPUT ;
    USE SIGNAL ;
    PORT
      LAYER M5 ;
        RECT  35.856 189.996 35.88 190.08 ;
    END
  END f_d[77]
  PIN f_d[78]
    DIRECTION INPUT ;
    USE SIGNAL ;
    PORT
      LAYER M5 ;
        RECT  36.144 189.996 36.168 190.08 ;
    END
  END f_d[78]
  PIN f_d[79]
    DIRECTION INPUT ;
    USE SIGNAL ;
    PORT
      LAYER M5 ;
        RECT  36.48 189.996 36.504 190.08 ;
    END
  END f_d[79]
  PIN f_d[7]
    DIRECTION INPUT ;
    USE SIGNAL ;
    PORT
      LAYER M5 ;
        RECT  14.832 189.996 14.856 190.08 ;
    END
  END f_d[7]
  PIN f_d[80]
    DIRECTION INPUT ;
    USE SIGNAL ;
    PORT
      LAYER M5 ;
        RECT  36.768 189.996 36.792 190.08 ;
    END
  END f_d[80]
  PIN f_d[81]
    DIRECTION INPUT ;
    USE SIGNAL ;
    PORT
      LAYER M5 ;
        RECT  37.056 189.996 37.08 190.08 ;
    END
  END f_d[81]
  PIN f_d[82]
    DIRECTION INPUT ;
    USE SIGNAL ;
    PORT
      LAYER M5 ;
        RECT  37.392 189.996 37.416 190.08 ;
    END
  END f_d[82]
  PIN f_d[83]
    DIRECTION INPUT ;
    USE SIGNAL ;
    PORT
      LAYER M5 ;
        RECT  37.68 189.996 37.704 190.08 ;
    END
  END f_d[83]
  PIN f_d[84]
    DIRECTION INPUT ;
    USE SIGNAL ;
    PORT
      LAYER M5 ;
        RECT  37.968 189.996 37.992 190.08 ;
    END
  END f_d[84]
  PIN f_d[85]
    DIRECTION INPUT ;
    USE SIGNAL ;
    PORT
      LAYER M5 ;
        RECT  38.256 189.996 38.28 190.08 ;
    END
  END f_d[85]
  PIN f_d[86]
    DIRECTION INPUT ;
    USE SIGNAL ;
    PORT
      LAYER M5 ;
        RECT  38.592 189.996 38.616 190.08 ;
    END
  END f_d[86]
  PIN f_d[87]
    DIRECTION INPUT ;
    USE SIGNAL ;
    PORT
      LAYER M5 ;
        RECT  38.88 189.996 38.904 190.08 ;
    END
  END f_d[87]
  PIN f_d[88]
    DIRECTION INPUT ;
    USE SIGNAL ;
    PORT
      LAYER M5 ;
        RECT  39.168 189.996 39.192 190.08 ;
    END
  END f_d[88]
  PIN f_d[89]
    DIRECTION INPUT ;
    USE SIGNAL ;
    PORT
      LAYER M5 ;
        RECT  39.456 189.996 39.48 190.08 ;
    END
  END f_d[89]
  PIN f_d[8]
    DIRECTION INPUT ;
    USE SIGNAL ;
    PORT
      LAYER M5 ;
        RECT  15.12 189.996 15.144 190.08 ;
    END
  END f_d[8]
  PIN f_d[90]
    DIRECTION INPUT ;
    USE SIGNAL ;
    PORT
      LAYER M5 ;
        RECT  39.792 189.996 39.816 190.08 ;
    END
  END f_d[90]
  PIN f_d[91]
    DIRECTION INPUT ;
    USE SIGNAL ;
    PORT
      LAYER M5 ;
        RECT  40.08 189.996 40.104 190.08 ;
    END
  END f_d[91]
  PIN f_d[92]
    DIRECTION INPUT ;
    USE SIGNAL ;
    PORT
      LAYER M5 ;
        RECT  40.368 189.996 40.392 190.08 ;
    END
  END f_d[92]
  PIN f_d[93]
    DIRECTION INPUT ;
    USE SIGNAL ;
    PORT
      LAYER M5 ;
        RECT  40.656 189.996 40.68 190.08 ;
    END
  END f_d[93]
  PIN f_d[94]
    DIRECTION INPUT ;
    USE SIGNAL ;
    PORT
      LAYER M5 ;
        RECT  40.992 189.996 41.016 190.08 ;
    END
  END f_d[94]
  PIN f_d[95]
    DIRECTION INPUT ;
    USE SIGNAL ;
    PORT
      LAYER M5 ;
        RECT  41.28 189.996 41.304 190.08 ;
    END
  END f_d[95]
  PIN f_d[96]
    DIRECTION INPUT ;
    USE SIGNAL ;
    PORT
      LAYER M5 ;
        RECT  41.568 189.996 41.592 190.08 ;
    END
  END f_d[96]
  PIN f_d[97]
    DIRECTION INPUT ;
    USE SIGNAL ;
    PORT
      LAYER M5 ;
        RECT  41.856 189.996 41.88 190.08 ;
    END
  END f_d[97]
  PIN f_d[98]
    DIRECTION INPUT ;
    USE SIGNAL ;
    PORT
      LAYER M5 ;
        RECT  42.192 189.996 42.216 190.08 ;
    END
  END f_d[98]
  PIN f_d[99]
    DIRECTION INPUT ;
    USE SIGNAL ;
    PORT
      LAYER M5 ;
        RECT  42.48 189.996 42.504 190.08 ;
    END
  END f_d[99]
  PIN f_d[9]
    DIRECTION INPUT ;
    USE SIGNAL ;
    PORT
      LAYER M5 ;
        RECT  15.456 189.996 15.48 190.08 ;
    END
  END f_d[9]
  PIN f_v[0]
    DIRECTION INPUT ;
    USE SIGNAL ;
    PORT
      LAYER M5 ;
        RECT  4.608 189.996 4.632 190.08 ;
    END
  END f_v[0]
  PIN f_v[1]
    DIRECTION INPUT ;
    USE SIGNAL ;
    PORT
      LAYER M5 ;
        RECT  4.944 189.996 4.968 190.08 ;
    END
  END f_v[1]
  PIN f_v[2]
    DIRECTION INPUT ;
    USE SIGNAL ;
    PORT
      LAYER M5 ;
        RECT  5.232 189.996 5.256 190.08 ;
    END
  END f_v[2]
  PIN fault
    DIRECTION OUTPUT ;
    USE SIGNAL ;
    PORT
      LAYER M5 ;
        RECT  177.072 189.996 177.096 190.08 ;
    END
  END fault
  PIN go
    DIRECTION INPUT ;
    USE SIGNAL ;
    PORT
      LAYER M5 ;
        RECT  4.32 189.996 4.344 190.08 ;
    END
  END go
  PIN r[0]
    DIRECTION OUTPUT ;
    USE SIGNAL ;
    PORT
      LAYER M5 ;
        RECT  167.472 189.996 167.496 190.08 ;
    END
  END r[0]
  PIN r[10]
    DIRECTION OUTPUT ;
    USE SIGNAL ;
    PORT
      LAYER M5 ;
        RECT  170.448 189.996 170.472 190.08 ;
    END
  END r[10]
  PIN r[11]
    DIRECTION OUTPUT ;
    USE SIGNAL ;
    PORT
      LAYER M5 ;
        RECT  170.784 189.996 170.808 190.08 ;
    END
  END r[11]
  PIN r[12]
    DIRECTION OUTPUT ;
    USE SIGNAL ;
    PORT
      LAYER M5 ;
        RECT  171.072 189.996 171.096 190.08 ;
    END
  END r[12]
  PIN r[13]
    DIRECTION OUTPUT ;
    USE SIGNAL ;
    PORT
      LAYER M5 ;
        RECT  171.36 189.996 171.384 190.08 ;
    END
  END r[13]
  PIN r[14]
    DIRECTION OUTPUT ;
    USE SIGNAL ;
    PORT
      LAYER M5 ;
        RECT  171.648 189.996 171.672 190.08 ;
    END
  END r[14]
  PIN r[15]
    DIRECTION OUTPUT ;
    USE SIGNAL ;
    PORT
      LAYER M5 ;
        RECT  171.984 189.996 172.008 190.08 ;
    END
  END r[15]
  PIN r[16]
    DIRECTION OUTPUT ;
    USE SIGNAL ;
    PORT
      LAYER M5 ;
        RECT  172.272 189.996 172.296 190.08 ;
    END
  END r[16]
  PIN r[17]
    DIRECTION OUTPUT ;
    USE SIGNAL ;
    PORT
      LAYER M5 ;
        RECT  172.56 189.996 172.584 190.08 ;
    END
  END r[17]
  PIN r[18]
    DIRECTION OUTPUT ;
    USE SIGNAL ;
    PORT
      LAYER M5 ;
        RECT  172.848 189.996 172.872 190.08 ;
    END
  END r[18]
  PIN r[19]
    DIRECTION OUTPUT ;
    USE SIGNAL ;
    PORT
      LAYER M5 ;
        RECT  173.184 189.996 173.208 190.08 ;
    END
  END r[19]
  PIN r[1]
    DIRECTION OUTPUT ;
    USE SIGNAL ;
    PORT
      LAYER M5 ;
        RECT  167.76 189.996 167.784 190.08 ;
    END
  END r[1]
  PIN r[20]
    DIRECTION OUTPUT ;
    USE SIGNAL ;
    PORT
      LAYER M5 ;
        RECT  173.472 189.996 173.496 190.08 ;
    END
  END r[20]
  PIN r[21]
    DIRECTION OUTPUT ;
    USE SIGNAL ;
    PORT
      LAYER M5 ;
        RECT  173.76 189.996 173.784 190.08 ;
    END
  END r[21]
  PIN r[22]
    DIRECTION OUTPUT ;
    USE SIGNAL ;
    PORT
      LAYER M5 ;
        RECT  174.048 189.996 174.072 190.08 ;
    END
  END r[22]
  PIN r[23]
    DIRECTION OUTPUT ;
    USE SIGNAL ;
    PORT
      LAYER M5 ;
        RECT  174.384 189.996 174.408 190.08 ;
    END
  END r[23]
  PIN r[24]
    DIRECTION OUTPUT ;
    USE SIGNAL ;
    PORT
      LAYER M5 ;
        RECT  174.672 189.996 174.696 190.08 ;
    END
  END r[24]
  PIN r[25]
    DIRECTION OUTPUT ;
    USE SIGNAL ;
    PORT
      LAYER M5 ;
        RECT  174.96 189.996 174.984 190.08 ;
    END
  END r[25]
  PIN r[26]
    DIRECTION OUTPUT ;
    USE SIGNAL ;
    PORT
      LAYER M5 ;
        RECT  175.248 189.996 175.272 190.08 ;
    END
  END r[26]
  PIN r[27]
    DIRECTION OUTPUT ;
    USE SIGNAL ;
    PORT
      LAYER M5 ;
        RECT  175.584 189.996 175.608 190.08 ;
    END
  END r[27]
  PIN r[28]
    DIRECTION OUTPUT ;
    USE SIGNAL ;
    PORT
      LAYER M5 ;
        RECT  175.872 189.996 175.896 190.08 ;
    END
  END r[28]
  PIN r[29]
    DIRECTION OUTPUT ;
    USE SIGNAL ;
    PORT
      LAYER M5 ;
        RECT  176.16 189.996 176.184 190.08 ;
    END
  END r[29]
  PIN r[2]
    DIRECTION OUTPUT ;
    USE SIGNAL ;
    PORT
      LAYER M5 ;
        RECT  168.048 189.996 168.072 190.08 ;
    END
  END r[2]
  PIN r[30]
    DIRECTION OUTPUT ;
    USE SIGNAL ;
    PORT
      LAYER M5 ;
        RECT  176.448 189.996 176.472 190.08 ;
    END
  END r[30]
  PIN r[31]
    DIRECTION OUTPUT ;
    USE SIGNAL ;
    PORT
      LAYER M5 ;
        RECT  176.784 189.996 176.808 190.08 ;
    END
  END r[31]
  PIN r[3]
    DIRECTION OUTPUT ;
    USE SIGNAL ;
    PORT
      LAYER M5 ;
        RECT  168.336 189.996 168.36 190.08 ;
    END
  END r[3]
  PIN r[4]
    DIRECTION OUTPUT ;
    USE SIGNAL ;
    PORT
      LAYER M5 ;
        RECT  168.672 189.996 168.696 190.08 ;
    END
  END r[4]
  PIN r[5]
    DIRECTION OUTPUT ;
    USE SIGNAL ;
    PORT
      LAYER M5 ;
        RECT  168.96 189.996 168.984 190.08 ;
    END
  END r[5]
  PIN r[6]
    DIRECTION OUTPUT ;
    USE SIGNAL ;
    PORT
      LAYER M5 ;
        RECT  169.248 189.996 169.272 190.08 ;
    END
  END r[6]
  PIN r[7]
    DIRECTION OUTPUT ;
    USE SIGNAL ;
    PORT
      LAYER M5 ;
        RECT  169.584 189.996 169.608 190.08 ;
    END
  END r[7]
  PIN r[8]
    DIRECTION OUTPUT ;
    USE SIGNAL ;
    PORT
      LAYER M5 ;
        RECT  169.872 189.996 169.896 190.08 ;
    END
  END r[8]
  PIN r[9]
    DIRECTION OUTPUT ;
    USE SIGNAL ;
    PORT
      LAYER M5 ;
        RECT  170.16 189.996 170.184 190.08 ;
    END
  END r[9]
  PIN r_v
    DIRECTION OUTPUT ;
    USE SIGNAL ;
    PORT
      LAYER M5 ;
        RECT  167.136 189.996 167.16 190.08 ;
    END
  END r_v
  PIN rst_n
    DIRECTION INPUT ;
    USE SIGNAL ;
    PORT
      LAYER M5 ;
        RECT  166.848 189.996 166.872 190.08 ;
    END
  END rst_n
  PIN VDD
    DIRECTION INOUT ;
    USE POWER ;
    PORT
      LAYER M5 ;
        RECT  174.996 4.311 175.116 185.769 ;
        RECT  170.676 4.311 170.796 185.769 ;
        RECT  166.356 4.311 166.476 185.769 ;
        RECT  162.036 4.311 162.156 185.769 ;
        RECT  157.716 4.311 157.836 185.769 ;
        RECT  153.396 4.311 153.516 185.769 ;
        RECT  149.076 4.311 149.196 185.769 ;
        RECT  144.756 4.311 144.876 185.769 ;
        RECT  140.436 4.311 140.556 185.769 ;
        RECT  136.116 4.311 136.236 185.769 ;
        RECT  131.796 4.311 131.916 185.769 ;
        RECT  127.476 4.311 127.596 185.769 ;
        RECT  123.156 4.311 123.276 185.769 ;
        RECT  118.836 4.311 118.956 185.769 ;
        RECT  114.516 4.311 114.636 185.769 ;
        RECT  110.196 4.311 110.316 185.769 ;
        RECT  105.876 4.311 105.996 185.769 ;
        RECT  101.556 4.311 101.676 185.769 ;
        RECT  97.236 4.311 97.356 185.769 ;
        RECT  92.916 4.311 93.036 185.769 ;
        RECT  88.596 4.311 88.716 185.769 ;
        RECT  84.276 4.311 84.396 185.769 ;
        RECT  79.956 4.311 80.076 185.769 ;
        RECT  75.636 4.311 75.756 185.769 ;
        RECT  71.316 4.311 71.436 185.769 ;
        RECT  66.996 4.311 67.116 185.769 ;
        RECT  62.676 4.311 62.796 185.769 ;
        RECT  58.356 4.311 58.476 185.769 ;
        RECT  54.036 4.311 54.156 185.769 ;
        RECT  49.716 4.311 49.836 185.769 ;
        RECT  45.396 4.311 45.516 185.769 ;
        RECT  41.076 4.311 41.196 185.769 ;
        RECT  36.756 4.311 36.876 185.769 ;
        RECT  32.436 4.311 32.556 185.769 ;
        RECT  28.116 4.311 28.236 185.769 ;
        RECT  23.796 4.311 23.916 185.769 ;
        RECT  19.476 4.311 19.596 185.769 ;
        RECT  15.156 4.311 15.276 185.769 ;
        RECT  10.836 4.311 10.956 185.769 ;
        RECT  6.516 4.311 6.636 185.769 ;
    END
  END VDD
  PIN VSS
    DIRECTION INOUT ;
    USE GROUND ;
    PORT
      LAYER M5 ;
        RECT  174.804 4.297 174.924 185.783 ;
        RECT  170.484 4.297 170.604 185.783 ;
        RECT  166.164 4.297 166.284 185.783 ;
        RECT  161.844 4.297 161.964 185.783 ;
        RECT  157.524 4.297 157.644 185.783 ;
        RECT  153.204 4.297 153.324 185.783 ;
        RECT  148.884 4.297 149.004 185.783 ;
        RECT  144.564 4.297 144.684 185.783 ;
        RECT  140.244 4.297 140.364 185.783 ;
        RECT  135.924 4.297 136.044 185.783 ;
        RECT  131.604 4.297 131.724 185.783 ;
        RECT  127.284 4.297 127.404 185.783 ;
        RECT  122.964 4.297 123.084 185.783 ;
        RECT  118.644 4.297 118.764 185.783 ;
        RECT  114.324 4.297 114.444 185.783 ;
        RECT  110.004 4.297 110.124 185.783 ;
        RECT  105.684 4.297 105.804 185.783 ;
        RECT  101.364 4.297 101.484 185.783 ;
        RECT  97.044 4.297 97.164 185.783 ;
        RECT  92.724 4.297 92.844 185.783 ;
        RECT  88.404 4.297 88.524 185.783 ;
        RECT  84.084 4.297 84.204 185.783 ;
        RECT  79.764 4.297 79.884 185.783 ;
        RECT  75.444 4.297 75.564 185.783 ;
        RECT  71.124 4.297 71.244 185.783 ;
        RECT  66.804 4.297 66.924 185.783 ;
        RECT  62.484 4.297 62.604 185.783 ;
        RECT  58.164 4.297 58.284 185.783 ;
        RECT  53.844 4.297 53.964 185.783 ;
        RECT  49.524 4.297 49.644 185.783 ;
        RECT  45.204 4.297 45.324 185.783 ;
        RECT  40.884 4.297 41.004 185.783 ;
        RECT  36.564 4.297 36.684 185.783 ;
        RECT  32.244 4.297 32.364 185.783 ;
        RECT  27.924 4.297 28.044 185.783 ;
        RECT  23.604 4.297 23.724 185.783 ;
        RECT  19.284 4.297 19.404 185.783 ;
        RECT  14.964 4.297 15.084 185.783 ;
        RECT  10.644 4.297 10.764 185.783 ;
        RECT  6.324 4.297 6.444 185.783 ;
    END
  END VSS
  OBS
    LAYER RVTN ;
     RECT  4.309 4.297 177.12 190.08 ;
    LAYER RVTP ;
     RECT  4.309 4.297 177.12 190.08 ;
    LAYER M1 ;
     RECT  4.309 4.297 177.12 190.08 ;
    LAYER M2 ;
     RECT  4.309 4.297 177.12 190.08 ;
    LAYER M3 ;
     RECT  4.309 4.297 177.12 190.08 ;
    LAYER M4 ;
     RECT  4.309 4.297 177.12 190.08 ;
    LAYER M5 ;
     RECT  4.309 4.297 177.12 190.08 ;
  END
END ot_s81dv_norm_finish
END LIBRARY
